VERSION 5.8 ;
BUSBITCHARS "[]" ;
DIVIDERCHAR "/" ;
UNITS
    DATABASE MICRONS 1000 ;
END UNITS

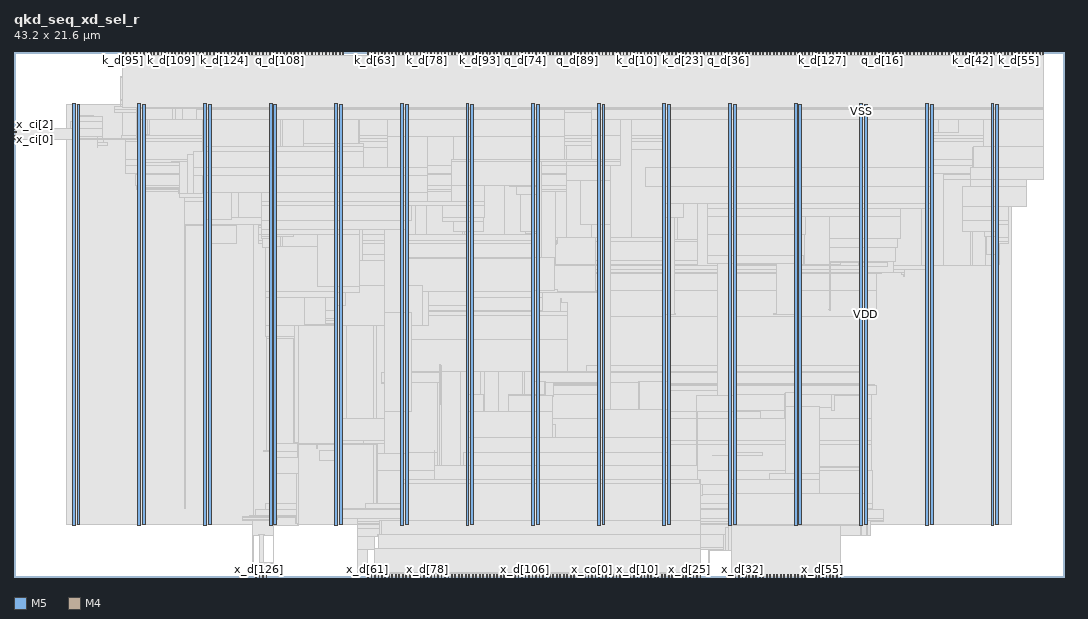
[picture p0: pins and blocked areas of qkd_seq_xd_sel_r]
MACRO qkd_seq_xd_sel_r
  FOREIGN qkd_seq_xd_sel_r 0 0 ;
  CLASS BLOCK ;
  SIZE 43.2 BY 21.6 ;
  PIN ck
    DIRECTION INPUT ;
    USE SIGNAL ;
    PORT
      LAYER M5 ;
        RECT  24.048 21.516 24.072 21.6 ;
    END
  END ck
  PIN k_d[0]
    DIRECTION INPUT ;
    USE SIGNAL ;
    PORT
      LAYER M5 ;
        RECT  24.192 21.516 24.216 21.6 ;
    END
  END k_d[0]
  PIN k_d[100]
    DIRECTION INPUT ;
    USE SIGNAL ;
    PORT
      LAYER M5 ;
        RECT  5.184 21.516 5.208 21.6 ;
    END
  END k_d[100]
  PIN k_d[101]
    DIRECTION INPUT ;
    USE SIGNAL ;
    PORT
      LAYER M5 ;
        RECT  5.328 21.516 5.352 21.6 ;
    END
  END k_d[101]
  PIN k_d[102]
    DIRECTION INPUT ;
    USE SIGNAL ;
    PORT
      LAYER M5 ;
        RECT  5.472 21.516 5.496 21.6 ;
    END
  END k_d[102]
  PIN k_d[103]
    DIRECTION INPUT ;
    USE SIGNAL ;
    PORT
      LAYER M5 ;
        RECT  5.616 21.516 5.64 21.6 ;
    END
  END k_d[103]
  PIN k_d[104]
    DIRECTION INPUT ;
    USE SIGNAL ;
    PORT
      LAYER M5 ;
        RECT  5.76 21.516 5.784 21.6 ;
    END
  END k_d[104]
  PIN k_d[105]
    DIRECTION INPUT ;
    USE SIGNAL ;
    PORT
      LAYER M5 ;
        RECT  5.904 21.516 5.928 21.6 ;
    END
  END k_d[105]
  PIN k_d[106]
    DIRECTION INPUT ;
    USE SIGNAL ;
    PORT
      LAYER M5 ;
        RECT  6.048 21.516 6.072 21.6 ;
    END
  END k_d[106]
  PIN k_d[107]
    DIRECTION INPUT ;
    USE SIGNAL ;
    PORT
      LAYER M5 ;
        RECT  6.192 21.516 6.216 21.6 ;
    END
  END k_d[107]
  PIN k_d[108]
    DIRECTION INPUT ;
    USE SIGNAL ;
    PORT
      LAYER M5 ;
        RECT  6.336 21.516 6.36 21.6 ;
    END
  END k_d[108]
  PIN k_d[109]
    DIRECTION INPUT ;
    USE SIGNAL ;
    PORT
      LAYER M5 ;
        RECT  6.48 21.516 6.504 21.6 ;
    END
  END k_d[109]
  PIN k_d[10]
    DIRECTION INPUT ;
    USE SIGNAL ;
    PORT
      LAYER M5 ;
        RECT  25.632 21.516 25.656 21.6 ;
    END
  END k_d[10]
  PIN k_d[110]
    DIRECTION INPUT ;
    USE SIGNAL ;
    PORT
      LAYER M5 ;
        RECT  6.624 21.516 6.648 21.6 ;
    END
  END k_d[110]
  PIN k_d[111]
    DIRECTION INPUT ;
    USE SIGNAL ;
    PORT
      LAYER M5 ;
        RECT  6.768 21.516 6.792 21.6 ;
    END
  END k_d[111]
  PIN k_d[112]
    DIRECTION INPUT ;
    USE SIGNAL ;
    PORT
      LAYER M5 ;
        RECT  6.912 21.516 6.936 21.6 ;
    END
  END k_d[112]
  PIN k_d[113]
    DIRECTION INPUT ;
    USE SIGNAL ;
    PORT
      LAYER M5 ;
        RECT  7.056 21.516 7.08 21.6 ;
    END
  END k_d[113]
  PIN k_d[114]
    DIRECTION INPUT ;
    USE SIGNAL ;
    PORT
      LAYER M5 ;
        RECT  7.2 21.516 7.224 21.6 ;
    END
  END k_d[114]
  PIN k_d[115]
    DIRECTION INPUT ;
    USE SIGNAL ;
    PORT
      LAYER M5 ;
        RECT  7.344 21.516 7.368 21.6 ;
    END
  END k_d[115]
  PIN k_d[116]
    DIRECTION INPUT ;
    USE SIGNAL ;
    PORT
      LAYER M5 ;
        RECT  7.488 21.516 7.512 21.6 ;
    END
  END k_d[116]
  PIN k_d[117]
    DIRECTION INPUT ;
    USE SIGNAL ;
    PORT
      LAYER M5 ;
        RECT  7.632 21.516 7.656 21.6 ;
    END
  END k_d[117]
  PIN k_d[118]
    DIRECTION INPUT ;
    USE SIGNAL ;
    PORT
      LAYER M5 ;
        RECT  7.776 21.516 7.8 21.6 ;
    END
  END k_d[118]
  PIN k_d[119]
    DIRECTION INPUT ;
    USE SIGNAL ;
    PORT
      LAYER M5 ;
        RECT  7.92 21.516 7.944 21.6 ;
    END
  END k_d[119]
  PIN k_d[11]
    DIRECTION INPUT ;
    USE SIGNAL ;
    PORT
      LAYER M5 ;
        RECT  25.776 21.516 25.8 21.6 ;
    END
  END k_d[11]
  PIN k_d[120]
    DIRECTION INPUT ;
    USE SIGNAL ;
    PORT
      LAYER M5 ;
        RECT  8.064 21.516 8.088 21.6 ;
    END
  END k_d[120]
  PIN k_d[121]
    DIRECTION INPUT ;
    USE SIGNAL ;
    PORT
      LAYER M5 ;
        RECT  8.208 21.516 8.232 21.6 ;
    END
  END k_d[121]
  PIN k_d[122]
    DIRECTION INPUT ;
    USE SIGNAL ;
    PORT
      LAYER M5 ;
        RECT  8.352 21.516 8.376 21.6 ;
    END
  END k_d[122]
  PIN k_d[123]
    DIRECTION INPUT ;
    USE SIGNAL ;
    PORT
      LAYER M5 ;
        RECT  8.496 21.516 8.52 21.6 ;
    END
  END k_d[123]
  PIN k_d[124]
    DIRECTION INPUT ;
    USE SIGNAL ;
    PORT
      LAYER M5 ;
        RECT  8.64 21.516 8.664 21.6 ;
    END
  END k_d[124]
  PIN k_d[125]
    DIRECTION INPUT ;
    USE SIGNAL ;
    PORT
      LAYER M5 ;
        RECT  8.784 21.516 8.808 21.6 ;
    END
  END k_d[125]
  PIN k_d[126]
    DIRECTION INPUT ;
    USE SIGNAL ;
    PORT
      LAYER M5 ;
        RECT  8.928 21.516 8.952 21.6 ;
    END
  END k_d[126]
  PIN k_d[127]
    DIRECTION INPUT ;
    USE SIGNAL ;
    PORT
      LAYER M5 ;
        RECT  33.264 21.516 33.288 21.6 ;
    END
  END k_d[127]
  PIN k_d[12]
    DIRECTION INPUT ;
    USE SIGNAL ;
    PORT
      LAYER M5 ;
        RECT  25.92 21.516 25.944 21.6 ;
    END
  END k_d[12]
  PIN k_d[13]
    DIRECTION INPUT ;
    USE SIGNAL ;
    PORT
      LAYER M5 ;
        RECT  26.064 21.516 26.088 21.6 ;
    END
  END k_d[13]
  PIN k_d[14]
    DIRECTION INPUT ;
    USE SIGNAL ;
    PORT
      LAYER M5 ;
        RECT  26.208 21.516 26.232 21.6 ;
    END
  END k_d[14]
  PIN k_d[15]
    DIRECTION INPUT ;
    USE SIGNAL ;
    PORT
      LAYER M5 ;
        RECT  26.352 21.516 26.376 21.6 ;
    END
  END k_d[15]
  PIN k_d[16]
    DIRECTION INPUT ;
    USE SIGNAL ;
    PORT
      LAYER M5 ;
        RECT  26.496 21.516 26.52 21.6 ;
    END
  END k_d[16]
  PIN k_d[17]
    DIRECTION INPUT ;
    USE SIGNAL ;
    PORT
      LAYER M5 ;
        RECT  26.64 21.516 26.664 21.6 ;
    END
  END k_d[17]
  PIN k_d[18]
    DIRECTION INPUT ;
    USE SIGNAL ;
    PORT
      LAYER M5 ;
        RECT  26.784 21.516 26.808 21.6 ;
    END
  END k_d[18]
  PIN k_d[19]
    DIRECTION INPUT ;
    USE SIGNAL ;
    PORT
      LAYER M5 ;
        RECT  26.928 21.516 26.952 21.6 ;
    END
  END k_d[19]
  PIN k_d[1]
    DIRECTION INPUT ;
    USE SIGNAL ;
    PORT
      LAYER M5 ;
        RECT  24.336 21.516 24.36 21.6 ;
    END
  END k_d[1]
  PIN k_d[20]
    DIRECTION INPUT ;
    USE SIGNAL ;
    PORT
      LAYER M5 ;
        RECT  27.072 21.516 27.096 21.6 ;
    END
  END k_d[20]
  PIN k_d[21]
    DIRECTION INPUT ;
    USE SIGNAL ;
    PORT
      LAYER M5 ;
        RECT  27.216 21.516 27.24 21.6 ;
    END
  END k_d[21]
  PIN k_d[22]
    DIRECTION INPUT ;
    USE SIGNAL ;
    PORT
      LAYER M5 ;
        RECT  27.36 21.516 27.384 21.6 ;
    END
  END k_d[22]
  PIN k_d[23]
    DIRECTION INPUT ;
    USE SIGNAL ;
    PORT
      LAYER M5 ;
        RECT  27.504 21.516 27.528 21.6 ;
    END
  END k_d[23]
  PIN k_d[24]
    DIRECTION INPUT ;
    USE SIGNAL ;
    PORT
      LAYER M5 ;
        RECT  27.648 21.516 27.672 21.6 ;
    END
  END k_d[24]
  PIN k_d[25]
    DIRECTION INPUT ;
    USE SIGNAL ;
    PORT
      LAYER M5 ;
        RECT  27.792 21.516 27.816 21.6 ;
    END
  END k_d[25]
  PIN k_d[26]
    DIRECTION INPUT ;
    USE SIGNAL ;
    PORT
      LAYER M5 ;
        RECT  27.936 21.516 27.96 21.6 ;
    END
  END k_d[26]
  PIN k_d[27]
    DIRECTION INPUT ;
    USE SIGNAL ;
    PORT
      LAYER M5 ;
        RECT  28.08 21.516 28.104 21.6 ;
    END
  END k_d[27]
  PIN k_d[28]
    DIRECTION INPUT ;
    USE SIGNAL ;
    PORT
      LAYER M5 ;
        RECT  28.224 21.516 28.248 21.6 ;
    END
  END k_d[28]
  PIN k_d[29]
    DIRECTION INPUT ;
    USE SIGNAL ;
    PORT
      LAYER M5 ;
        RECT  28.368 21.516 28.392 21.6 ;
    END
  END k_d[29]
  PIN k_d[2]
    DIRECTION INPUT ;
    USE SIGNAL ;
    PORT
      LAYER M5 ;
        RECT  24.48 21.516 24.504 21.6 ;
    END
  END k_d[2]
  PIN k_d[30]
    DIRECTION INPUT ;
    USE SIGNAL ;
    PORT
      LAYER M5 ;
        RECT  28.512 21.516 28.536 21.6 ;
    END
  END k_d[30]
  PIN k_d[31]
    DIRECTION INPUT ;
    USE SIGNAL ;
    PORT
      LAYER M5 ;
        RECT  37.872 21.516 37.896 21.6 ;
    END
  END k_d[31]
  PIN k_d[32]
    DIRECTION INPUT ;
    USE SIGNAL ;
    PORT
      LAYER M5 ;
        RECT  38.016 21.516 38.04 21.6 ;
    END
  END k_d[32]
  PIN k_d[33]
    DIRECTION INPUT ;
    USE SIGNAL ;
    PORT
      LAYER M5 ;
        RECT  38.16 21.516 38.184 21.6 ;
    END
  END k_d[33]
  PIN k_d[34]
    DIRECTION INPUT ;
    USE SIGNAL ;
    PORT
      LAYER M5 ;
        RECT  38.304 21.516 38.328 21.6 ;
    END
  END k_d[34]
  PIN k_d[35]
    DIRECTION INPUT ;
    USE SIGNAL ;
    PORT
      LAYER M5 ;
        RECT  38.448 21.516 38.472 21.6 ;
    END
  END k_d[35]
  PIN k_d[36]
    DIRECTION INPUT ;
    USE SIGNAL ;
    PORT
      LAYER M5 ;
        RECT  38.592 21.516 38.616 21.6 ;
    END
  END k_d[36]
  PIN k_d[37]
    DIRECTION INPUT ;
    USE SIGNAL ;
    PORT
      LAYER M5 ;
        RECT  38.736 21.516 38.76 21.6 ;
    END
  END k_d[37]
  PIN k_d[38]
    DIRECTION INPUT ;
    USE SIGNAL ;
    PORT
      LAYER M5 ;
        RECT  38.88 21.516 38.904 21.6 ;
    END
  END k_d[38]
  PIN k_d[39]
    DIRECTION INPUT ;
    USE SIGNAL ;
    PORT
      LAYER M5 ;
        RECT  39.024 21.516 39.048 21.6 ;
    END
  END k_d[39]
  PIN k_d[3]
    DIRECTION INPUT ;
    USE SIGNAL ;
    PORT
      LAYER M5 ;
        RECT  24.624 21.516 24.648 21.6 ;
    END
  END k_d[3]
  PIN k_d[40]
    DIRECTION INPUT ;
    USE SIGNAL ;
    PORT
      LAYER M5 ;
        RECT  39.168 21.516 39.192 21.6 ;
    END
  END k_d[40]
  PIN k_d[41]
    DIRECTION INPUT ;
    USE SIGNAL ;
    PORT
      LAYER M5 ;
        RECT  39.312 21.516 39.336 21.6 ;
    END
  END k_d[41]
  PIN k_d[42]
    DIRECTION INPUT ;
    USE SIGNAL ;
    PORT
      LAYER M5 ;
        RECT  39.456 21.516 39.48 21.6 ;
    END
  END k_d[42]
  PIN k_d[43]
    DIRECTION INPUT ;
    USE SIGNAL ;
    PORT
      LAYER M5 ;
        RECT  39.6 21.516 39.624 21.6 ;
    END
  END k_d[43]
  PIN k_d[44]
    DIRECTION INPUT ;
    USE SIGNAL ;
    PORT
      LAYER M5 ;
        RECT  39.744 21.516 39.768 21.6 ;
    END
  END k_d[44]
  PIN k_d[45]
    DIRECTION INPUT ;
    USE SIGNAL ;
    PORT
      LAYER M5 ;
        RECT  39.888 21.516 39.912 21.6 ;
    END
  END k_d[45]
  PIN k_d[46]
    DIRECTION INPUT ;
    USE SIGNAL ;
    PORT
      LAYER M5 ;
        RECT  40.032 21.516 40.056 21.6 ;
    END
  END k_d[46]
  PIN k_d[47]
    DIRECTION INPUT ;
    USE SIGNAL ;
    PORT
      LAYER M5 ;
        RECT  40.176 21.516 40.2 21.6 ;
    END
  END k_d[47]
  PIN k_d[48]
    DIRECTION INPUT ;
    USE SIGNAL ;
    PORT
      LAYER M5 ;
        RECT  40.32 21.516 40.344 21.6 ;
    END
  END k_d[48]
  PIN k_d[49]
    DIRECTION INPUT ;
    USE SIGNAL ;
    PORT
      LAYER M5 ;
        RECT  40.464 21.516 40.488 21.6 ;
    END
  END k_d[49]
  PIN k_d[4]
    DIRECTION INPUT ;
    USE SIGNAL ;
    PORT
      LAYER M5 ;
        RECT  24.768 21.516 24.792 21.6 ;
    END
  END k_d[4]
  PIN k_d[50]
    DIRECTION INPUT ;
    USE SIGNAL ;
    PORT
      LAYER M5 ;
        RECT  40.608 21.516 40.632 21.6 ;
    END
  END k_d[50]
  PIN k_d[51]
    DIRECTION INPUT ;
    USE SIGNAL ;
    PORT
      LAYER M5 ;
        RECT  40.752 21.516 40.776 21.6 ;
    END
  END k_d[51]
  PIN k_d[52]
    DIRECTION INPUT ;
    USE SIGNAL ;
    PORT
      LAYER M5 ;
        RECT  40.896 21.516 40.92 21.6 ;
    END
  END k_d[52]
  PIN k_d[53]
    DIRECTION INPUT ;
    USE SIGNAL ;
    PORT
      LAYER M5 ;
        RECT  41.04 21.516 41.064 21.6 ;
    END
  END k_d[53]
  PIN k_d[54]
    DIRECTION INPUT ;
    USE SIGNAL ;
    PORT
      LAYER M5 ;
        RECT  41.184 21.516 41.208 21.6 ;
    END
  END k_d[54]
  PIN k_d[55]
    DIRECTION INPUT ;
    USE SIGNAL ;
    PORT
      LAYER M5 ;
        RECT  41.328 21.516 41.352 21.6 ;
    END
  END k_d[55]
  PIN k_d[56]
    DIRECTION INPUT ;
    USE SIGNAL ;
    PORT
      LAYER M5 ;
        RECT  41.472 21.516 41.496 21.6 ;
    END
  END k_d[56]
  PIN k_d[57]
    DIRECTION INPUT ;
    USE SIGNAL ;
    PORT
      LAYER M5 ;
        RECT  41.616 21.516 41.64 21.6 ;
    END
  END k_d[57]
  PIN k_d[58]
    DIRECTION INPUT ;
    USE SIGNAL ;
    PORT
      LAYER M5 ;
        RECT  41.76 21.516 41.784 21.6 ;
    END
  END k_d[58]
  PIN k_d[59]
    DIRECTION INPUT ;
    USE SIGNAL ;
    PORT
      LAYER M5 ;
        RECT  41.904 21.516 41.928 21.6 ;
    END
  END k_d[59]
  PIN k_d[5]
    DIRECTION INPUT ;
    USE SIGNAL ;
    PORT
      LAYER M5 ;
        RECT  24.912 21.516 24.936 21.6 ;
    END
  END k_d[5]
  PIN k_d[60]
    DIRECTION INPUT ;
    USE SIGNAL ;
    PORT
      LAYER M5 ;
        RECT  42.048 21.516 42.072 21.6 ;
    END
  END k_d[60]
  PIN k_d[61]
    DIRECTION INPUT ;
    USE SIGNAL ;
    PORT
      LAYER M5 ;
        RECT  42.192 21.516 42.216 21.6 ;
    END
  END k_d[61]
  PIN k_d[62]
    DIRECTION INPUT ;
    USE SIGNAL ;
    PORT
      LAYER M5 ;
        RECT  42.336 21.516 42.36 21.6 ;
    END
  END k_d[62]
  PIN k_d[63]
    DIRECTION INPUT ;
    USE SIGNAL ;
    PORT
      LAYER M5 ;
        RECT  14.832 21.516 14.856 21.6 ;
    END
  END k_d[63]
  PIN k_d[64]
    DIRECTION INPUT ;
    USE SIGNAL ;
    PORT
      LAYER M5 ;
        RECT  14.976 21.516 15 21.6 ;
    END
  END k_d[64]
  PIN k_d[65]
    DIRECTION INPUT ;
    USE SIGNAL ;
    PORT
      LAYER M5 ;
        RECT  15.12 21.516 15.144 21.6 ;
    END
  END k_d[65]
  PIN k_d[66]
    DIRECTION INPUT ;
    USE SIGNAL ;
    PORT
      LAYER M5 ;
        RECT  15.264 21.516 15.288 21.6 ;
    END
  END k_d[66]
  PIN k_d[67]
    DIRECTION INPUT ;
    USE SIGNAL ;
    PORT
      LAYER M5 ;
        RECT  15.408 21.516 15.432 21.6 ;
    END
  END k_d[67]
  PIN k_d[68]
    DIRECTION INPUT ;
    USE SIGNAL ;
    PORT
      LAYER M5 ;
        RECT  15.552 21.516 15.576 21.6 ;
    END
  END k_d[68]
  PIN k_d[69]
    DIRECTION INPUT ;
    USE SIGNAL ;
    PORT
      LAYER M5 ;
        RECT  15.696 21.516 15.72 21.6 ;
    END
  END k_d[69]
  PIN k_d[6]
    DIRECTION INPUT ;
    USE SIGNAL ;
    PORT
      LAYER M5 ;
        RECT  25.056 21.516 25.08 21.6 ;
    END
  END k_d[6]
  PIN k_d[70]
    DIRECTION INPUT ;
    USE SIGNAL ;
    PORT
      LAYER M5 ;
        RECT  15.84 21.516 15.864 21.6 ;
    END
  END k_d[70]
  PIN k_d[71]
    DIRECTION INPUT ;
    USE SIGNAL ;
    PORT
      LAYER M5 ;
        RECT  15.984 21.516 16.008 21.6 ;
    END
  END k_d[71]
  PIN k_d[72]
    DIRECTION INPUT ;
    USE SIGNAL ;
    PORT
      LAYER M5 ;
        RECT  16.128 21.516 16.152 21.6 ;
    END
  END k_d[72]
  PIN k_d[73]
    DIRECTION INPUT ;
    USE SIGNAL ;
    PORT
      LAYER M5 ;
        RECT  16.272 21.516 16.296 21.6 ;
    END
  END k_d[73]
  PIN k_d[74]
    DIRECTION INPUT ;
    USE SIGNAL ;
    PORT
      LAYER M5 ;
        RECT  16.416 21.516 16.44 21.6 ;
    END
  END k_d[74]
  PIN k_d[75]
    DIRECTION INPUT ;
    USE SIGNAL ;
    PORT
      LAYER M5 ;
        RECT  16.56 21.516 16.584 21.6 ;
    END
  END k_d[75]
  PIN k_d[76]
    DIRECTION INPUT ;
    USE SIGNAL ;
    PORT
      LAYER M5 ;
        RECT  16.704 21.516 16.728 21.6 ;
    END
  END k_d[76]
  PIN k_d[77]
    DIRECTION INPUT ;
    USE SIGNAL ;
    PORT
      LAYER M5 ;
        RECT  16.848 21.516 16.872 21.6 ;
    END
  END k_d[77]
  PIN k_d[78]
    DIRECTION INPUT ;
    USE SIGNAL ;
    PORT
      LAYER M5 ;
        RECT  16.992 21.516 17.016 21.6 ;
    END
  END k_d[78]
  PIN k_d[79]
    DIRECTION INPUT ;
    USE SIGNAL ;
    PORT
      LAYER M5 ;
        RECT  17.136 21.516 17.16 21.6 ;
    END
  END k_d[79]
  PIN k_d[7]
    DIRECTION INPUT ;
    USE SIGNAL ;
    PORT
      LAYER M5 ;
        RECT  25.2 21.516 25.224 21.6 ;
    END
  END k_d[7]
  PIN k_d[80]
    DIRECTION INPUT ;
    USE SIGNAL ;
    PORT
      LAYER M5 ;
        RECT  17.28 21.516 17.304 21.6 ;
    END
  END k_d[80]
  PIN k_d[81]
    DIRECTION INPUT ;
    USE SIGNAL ;
    PORT
      LAYER M5 ;
        RECT  17.424 21.516 17.448 21.6 ;
    END
  END k_d[81]
  PIN k_d[82]
    DIRECTION INPUT ;
    USE SIGNAL ;
    PORT
      LAYER M5 ;
        RECT  17.568 21.516 17.592 21.6 ;
    END
  END k_d[82]
  PIN k_d[83]
    DIRECTION INPUT ;
    USE SIGNAL ;
    PORT
      LAYER M5 ;
        RECT  17.712 21.516 17.736 21.6 ;
    END
  END k_d[83]
  PIN k_d[84]
    DIRECTION INPUT ;
    USE SIGNAL ;
    PORT
      LAYER M5 ;
        RECT  17.856 21.516 17.88 21.6 ;
    END
  END k_d[84]
  PIN k_d[85]
    DIRECTION INPUT ;
    USE SIGNAL ;
    PORT
      LAYER M5 ;
        RECT  18 21.516 18.024 21.6 ;
    END
  END k_d[85]
  PIN k_d[86]
    DIRECTION INPUT ;
    USE SIGNAL ;
    PORT
      LAYER M5 ;
        RECT  18.144 21.516 18.168 21.6 ;
    END
  END k_d[86]
  PIN k_d[87]
    DIRECTION INPUT ;
    USE SIGNAL ;
    PORT
      LAYER M5 ;
        RECT  18.288 21.516 18.312 21.6 ;
    END
  END k_d[87]
  PIN k_d[88]
    DIRECTION INPUT ;
    USE SIGNAL ;
    PORT
      LAYER M5 ;
        RECT  18.432 21.516 18.456 21.6 ;
    END
  END k_d[88]
  PIN k_d[89]
    DIRECTION INPUT ;
    USE SIGNAL ;
    PORT
      LAYER M5 ;
        RECT  18.576 21.516 18.6 21.6 ;
    END
  END k_d[89]
  PIN k_d[8]
    DIRECTION INPUT ;
    USE SIGNAL ;
    PORT
      LAYER M5 ;
        RECT  25.344 21.516 25.368 21.6 ;
    END
  END k_d[8]
  PIN k_d[90]
    DIRECTION INPUT ;
    USE SIGNAL ;
    PORT
      LAYER M5 ;
        RECT  18.72 21.516 18.744 21.6 ;
    END
  END k_d[90]
  PIN k_d[91]
    DIRECTION INPUT ;
    USE SIGNAL ;
    PORT
      LAYER M5 ;
        RECT  18.864 21.516 18.888 21.6 ;
    END
  END k_d[91]
  PIN k_d[92]
    DIRECTION INPUT ;
    USE SIGNAL ;
    PORT
      LAYER M5 ;
        RECT  19.008 21.516 19.032 21.6 ;
    END
  END k_d[92]
  PIN k_d[93]
    DIRECTION INPUT ;
    USE SIGNAL ;
    PORT
      LAYER M5 ;
        RECT  19.152 21.516 19.176 21.6 ;
    END
  END k_d[93]
  PIN k_d[94]
    DIRECTION INPUT ;
    USE SIGNAL ;
    PORT
      LAYER M5 ;
        RECT  19.296 21.516 19.32 21.6 ;
    END
  END k_d[94]
  PIN k_d[95]
    DIRECTION INPUT ;
    USE SIGNAL ;
    PORT
      LAYER M5 ;
        RECT  4.464 21.516 4.488 21.6 ;
    END
  END k_d[95]
  PIN k_d[96]
    DIRECTION INPUT ;
    USE SIGNAL ;
    PORT
      LAYER M5 ;
        RECT  4.608 21.516 4.632 21.6 ;
    END
  END k_d[96]
  PIN k_d[97]
    DIRECTION INPUT ;
    USE SIGNAL ;
    PORT
      LAYER M5 ;
        RECT  4.752 21.516 4.776 21.6 ;
    END
  END k_d[97]
  PIN k_d[98]
    DIRECTION INPUT ;
    USE SIGNAL ;
    PORT
      LAYER M5 ;
        RECT  4.896 21.516 4.92 21.6 ;
    END
  END k_d[98]
  PIN k_d[99]
    DIRECTION INPUT ;
    USE SIGNAL ;
    PORT
      LAYER M5 ;
        RECT  5.04 21.516 5.064 21.6 ;
    END
  END k_d[99]
  PIN k_d[9]
    DIRECTION INPUT ;
    USE SIGNAL ;
    PORT
      LAYER M5 ;
        RECT  25.488 21.516 25.512 21.6 ;
    END
  END k_d[9]
  PIN q_d[0]
    DIRECTION INPUT ;
    USE SIGNAL ;
    PORT
      LAYER M5 ;
        RECT  33.408 21.516 33.432 21.6 ;
    END
  END q_d[0]
  PIN q_d[100]
    DIRECTION INPUT ;
    USE SIGNAL ;
    PORT
      LAYER M5 ;
        RECT  9.792 21.516 9.816 21.6 ;
    END
  END q_d[100]
  PIN q_d[101]
    DIRECTION INPUT ;
    USE SIGNAL ;
    PORT
      LAYER M5 ;
        RECT  9.936 21.516 9.96 21.6 ;
    END
  END q_d[101]
  PIN q_d[102]
    DIRECTION INPUT ;
    USE SIGNAL ;
    PORT
      LAYER M5 ;
        RECT  10.08 21.516 10.104 21.6 ;
    END
  END q_d[102]
  PIN q_d[103]
    DIRECTION INPUT ;
    USE SIGNAL ;
    PORT
      LAYER M5 ;
        RECT  10.224 21.516 10.248 21.6 ;
    END
  END q_d[103]
  PIN q_d[104]
    DIRECTION INPUT ;
    USE SIGNAL ;
    PORT
      LAYER M5 ;
        RECT  10.368 21.516 10.392 21.6 ;
    END
  END q_d[104]
  PIN q_d[105]
    DIRECTION INPUT ;
    USE SIGNAL ;
    PORT
      LAYER M5 ;
        RECT  10.512 21.516 10.536 21.6 ;
    END
  END q_d[105]
  PIN q_d[106]
    DIRECTION INPUT ;
    USE SIGNAL ;
    PORT
      LAYER M5 ;
        RECT  10.656 21.516 10.68 21.6 ;
    END
  END q_d[106]
  PIN q_d[107]
    DIRECTION INPUT ;
    USE SIGNAL ;
    PORT
      LAYER M5 ;
        RECT  10.8 21.516 10.824 21.6 ;
    END
  END q_d[107]
  PIN q_d[108]
    DIRECTION INPUT ;
    USE SIGNAL ;
    PORT
      LAYER M5 ;
        RECT  10.944 21.516 10.968 21.6 ;
    END
  END q_d[108]
  PIN q_d[109]
    DIRECTION INPUT ;
    USE SIGNAL ;
    PORT
      LAYER M5 ;
        RECT  11.088 21.516 11.112 21.6 ;
    END
  END q_d[109]
  PIN q_d[10]
    DIRECTION INPUT ;
    USE SIGNAL ;
    PORT
      LAYER M5 ;
        RECT  34.848 21.516 34.872 21.6 ;
    END
  END q_d[10]
  PIN q_d[110]
    DIRECTION INPUT ;
    USE SIGNAL ;
    PORT
      LAYER M5 ;
        RECT  11.232 21.516 11.256 21.6 ;
    END
  END q_d[110]
  PIN q_d[111]
    DIRECTION INPUT ;
    USE SIGNAL ;
    PORT
      LAYER M5 ;
        RECT  11.376 21.516 11.4 21.6 ;
    END
  END q_d[111]
  PIN q_d[112]
    DIRECTION INPUT ;
    USE SIGNAL ;
    PORT
      LAYER M5 ;
        RECT  11.52 21.516 11.544 21.6 ;
    END
  END q_d[112]
  PIN q_d[113]
    DIRECTION INPUT ;
    USE SIGNAL ;
    PORT
      LAYER M5 ;
        RECT  11.664 21.516 11.688 21.6 ;
    END
  END q_d[113]
  PIN q_d[114]
    DIRECTION INPUT ;
    USE SIGNAL ;
    PORT
      LAYER M5 ;
        RECT  11.808 21.516 11.832 21.6 ;
    END
  END q_d[114]
  PIN q_d[115]
    DIRECTION INPUT ;
    USE SIGNAL ;
    PORT
      LAYER M5 ;
        RECT  11.952 21.516 11.976 21.6 ;
    END
  END q_d[115]
  PIN q_d[116]
    DIRECTION INPUT ;
    USE SIGNAL ;
    PORT
      LAYER M5 ;
        RECT  12.096 21.516 12.12 21.6 ;
    END
  END q_d[116]
  PIN q_d[117]
    DIRECTION INPUT ;
    USE SIGNAL ;
    PORT
      LAYER M5 ;
        RECT  12.24 21.516 12.264 21.6 ;
    END
  END q_d[117]
  PIN q_d[118]
    DIRECTION INPUT ;
    USE SIGNAL ;
    PORT
      LAYER M5 ;
        RECT  12.384 21.516 12.408 21.6 ;
    END
  END q_d[118]
  PIN q_d[119]
    DIRECTION INPUT ;
    USE SIGNAL ;
    PORT
      LAYER M5 ;
        RECT  12.528 21.516 12.552 21.6 ;
    END
  END q_d[119]
  PIN q_d[11]
    DIRECTION INPUT ;
    USE SIGNAL ;
    PORT
      LAYER M5 ;
        RECT  34.992 21.516 35.016 21.6 ;
    END
  END q_d[11]
  PIN q_d[120]
    DIRECTION INPUT ;
    USE SIGNAL ;
    PORT
      LAYER M5 ;
        RECT  12.672 21.516 12.696 21.6 ;
    END
  END q_d[120]
  PIN q_d[121]
    DIRECTION INPUT ;
    USE SIGNAL ;
    PORT
      LAYER M5 ;
        RECT  12.816 21.516 12.84 21.6 ;
    END
  END q_d[121]
  PIN q_d[122]
    DIRECTION INPUT ;
    USE SIGNAL ;
    PORT
      LAYER M5 ;
        RECT  12.96 21.516 12.984 21.6 ;
    END
  END q_d[122]
  PIN q_d[123]
    DIRECTION INPUT ;
    USE SIGNAL ;
    PORT
      LAYER M5 ;
        RECT  13.104 21.516 13.128 21.6 ;
    END
  END q_d[123]
  PIN q_d[124]
    DIRECTION INPUT ;
    USE SIGNAL ;
    PORT
      LAYER M5 ;
        RECT  13.248 21.516 13.272 21.6 ;
    END
  END q_d[124]
  PIN q_d[125]
    DIRECTION INPUT ;
    USE SIGNAL ;
    PORT
      LAYER M5 ;
        RECT  13.392 21.516 13.416 21.6 ;
    END
  END q_d[125]
  PIN q_d[126]
    DIRECTION INPUT ;
    USE SIGNAL ;
    PORT
      LAYER M5 ;
        RECT  13.536 21.516 13.56 21.6 ;
    END
  END q_d[126]
  PIN q_d[127]
    DIRECTION INPUT ;
    USE SIGNAL ;
    PORT
      LAYER M5 ;
        RECT  14.544 21.516 14.568 21.6 ;
    END
  END q_d[127]
  PIN q_d[12]
    DIRECTION INPUT ;
    USE SIGNAL ;
    PORT
      LAYER M5 ;
        RECT  35.136 21.516 35.16 21.6 ;
    END
  END q_d[12]
  PIN q_d[13]
    DIRECTION INPUT ;
    USE SIGNAL ;
    PORT
      LAYER M5 ;
        RECT  35.28 21.516 35.304 21.6 ;
    END
  END q_d[13]
  PIN q_d[14]
    DIRECTION INPUT ;
    USE SIGNAL ;
    PORT
      LAYER M5 ;
        RECT  35.424 21.516 35.448 21.6 ;
    END
  END q_d[14]
  PIN q_d[15]
    DIRECTION INPUT ;
    USE SIGNAL ;
    PORT
      LAYER M5 ;
        RECT  35.568 21.516 35.592 21.6 ;
    END
  END q_d[15]
  PIN q_d[16]
    DIRECTION INPUT ;
    USE SIGNAL ;
    PORT
      LAYER M5 ;
        RECT  35.712 21.516 35.736 21.6 ;
    END
  END q_d[16]
  PIN q_d[17]
    DIRECTION INPUT ;
    USE SIGNAL ;
    PORT
      LAYER M5 ;
        RECT  35.856 21.516 35.88 21.6 ;
    END
  END q_d[17]
  PIN q_d[18]
    DIRECTION INPUT ;
    USE SIGNAL ;
    PORT
      LAYER M5 ;
        RECT  36 21.516 36.024 21.6 ;
    END
  END q_d[18]
  PIN q_d[19]
    DIRECTION INPUT ;
    USE SIGNAL ;
    PORT
      LAYER M5 ;
        RECT  36.144 21.516 36.168 21.6 ;
    END
  END q_d[19]
  PIN q_d[1]
    DIRECTION INPUT ;
    USE SIGNAL ;
    PORT
      LAYER M5 ;
        RECT  33.552 21.516 33.576 21.6 ;
    END
  END q_d[1]
  PIN q_d[20]
    DIRECTION INPUT ;
    USE SIGNAL ;
    PORT
      LAYER M5 ;
        RECT  36.288 21.516 36.312 21.6 ;
    END
  END q_d[20]
  PIN q_d[21]
    DIRECTION INPUT ;
    USE SIGNAL ;
    PORT
      LAYER M5 ;
        RECT  36.432 21.516 36.456 21.6 ;
    END
  END q_d[21]
  PIN q_d[22]
    DIRECTION INPUT ;
    USE SIGNAL ;
    PORT
      LAYER M5 ;
        RECT  36.576 21.516 36.6 21.6 ;
    END
  END q_d[22]
  PIN q_d[23]
    DIRECTION INPUT ;
    USE SIGNAL ;
    PORT
      LAYER M5 ;
        RECT  36.72 21.516 36.744 21.6 ;
    END
  END q_d[23]
  PIN q_d[24]
    DIRECTION INPUT ;
    USE SIGNAL ;
    PORT
      LAYER M5 ;
        RECT  36.864 21.516 36.888 21.6 ;
    END
  END q_d[24]
  PIN q_d[25]
    DIRECTION INPUT ;
    USE SIGNAL ;
    PORT
      LAYER M5 ;
        RECT  37.008 21.516 37.032 21.6 ;
    END
  END q_d[25]
  PIN q_d[26]
    DIRECTION INPUT ;
    USE SIGNAL ;
    PORT
      LAYER M5 ;
        RECT  37.152 21.516 37.176 21.6 ;
    END
  END q_d[26]
  PIN q_d[27]
    DIRECTION INPUT ;
    USE SIGNAL ;
    PORT
      LAYER M5 ;
        RECT  37.296 21.516 37.32 21.6 ;
    END
  END q_d[27]
  PIN q_d[28]
    DIRECTION INPUT ;
    USE SIGNAL ;
    PORT
      LAYER M5 ;
        RECT  37.44 21.516 37.464 21.6 ;
    END
  END q_d[28]
  PIN q_d[29]
    DIRECTION INPUT ;
    USE SIGNAL ;
    PORT
      LAYER M5 ;
        RECT  37.584 21.516 37.608 21.6 ;
    END
  END q_d[29]
  PIN q_d[2]
    DIRECTION INPUT ;
    USE SIGNAL ;
    PORT
      LAYER M5 ;
        RECT  33.696 21.516 33.72 21.6 ;
    END
  END q_d[2]
  PIN q_d[30]
    DIRECTION INPUT ;
    USE SIGNAL ;
    PORT
      LAYER M5 ;
        RECT  37.728 21.516 37.752 21.6 ;
    END
  END q_d[30]
  PIN q_d[31]
    DIRECTION INPUT ;
    USE SIGNAL ;
    PORT
      LAYER M5 ;
        RECT  28.656 21.516 28.68 21.6 ;
    END
  END q_d[31]
  PIN q_d[32]
    DIRECTION INPUT ;
    USE SIGNAL ;
    PORT
      LAYER M5 ;
        RECT  28.8 21.516 28.824 21.6 ;
    END
  END q_d[32]
  PIN q_d[33]
    DIRECTION INPUT ;
    USE SIGNAL ;
    PORT
      LAYER M5 ;
        RECT  28.944 21.516 28.968 21.6 ;
    END
  END q_d[33]
  PIN q_d[34]
    DIRECTION INPUT ;
    USE SIGNAL ;
    PORT
      LAYER M5 ;
        RECT  29.088 21.516 29.112 21.6 ;
    END
  END q_d[34]
  PIN q_d[35]
    DIRECTION INPUT ;
    USE SIGNAL ;
    PORT
      LAYER M5 ;
        RECT  29.232 21.516 29.256 21.6 ;
    END
  END q_d[35]
  PIN q_d[36]
    DIRECTION INPUT ;
    USE SIGNAL ;
    PORT
      LAYER M5 ;
        RECT  29.376 21.516 29.4 21.6 ;
    END
  END q_d[36]
  PIN q_d[37]
    DIRECTION INPUT ;
    USE SIGNAL ;
    PORT
      LAYER M5 ;
        RECT  29.52 21.516 29.544 21.6 ;
    END
  END q_d[37]
  PIN q_d[38]
    DIRECTION INPUT ;
    USE SIGNAL ;
    PORT
      LAYER M5 ;
        RECT  29.664 21.516 29.688 21.6 ;
    END
  END q_d[38]
  PIN q_d[39]
    DIRECTION INPUT ;
    USE SIGNAL ;
    PORT
      LAYER M5 ;
        RECT  29.808 21.516 29.832 21.6 ;
    END
  END q_d[39]
  PIN q_d[3]
    DIRECTION INPUT ;
    USE SIGNAL ;
    PORT
      LAYER M5 ;
        RECT  33.84 21.516 33.864 21.6 ;
    END
  END q_d[3]
  PIN q_d[40]
    DIRECTION INPUT ;
    USE SIGNAL ;
    PORT
      LAYER M5 ;
        RECT  29.952 21.516 29.976 21.6 ;
    END
  END q_d[40]
  PIN q_d[41]
    DIRECTION INPUT ;
    USE SIGNAL ;
    PORT
      LAYER M5 ;
        RECT  30.096 21.516 30.12 21.6 ;
    END
  END q_d[41]
  PIN q_d[42]
    DIRECTION INPUT ;
    USE SIGNAL ;
    PORT
      LAYER M5 ;
        RECT  30.24 21.516 30.264 21.6 ;
    END
  END q_d[42]
  PIN q_d[43]
    DIRECTION INPUT ;
    USE SIGNAL ;
    PORT
      LAYER M5 ;
        RECT  30.384 21.516 30.408 21.6 ;
    END
  END q_d[43]
  PIN q_d[44]
    DIRECTION INPUT ;
    USE SIGNAL ;
    PORT
      LAYER M5 ;
        RECT  30.528 21.516 30.552 21.6 ;
    END
  END q_d[44]
  PIN q_d[45]
    DIRECTION INPUT ;
    USE SIGNAL ;
    PORT
      LAYER M5 ;
        RECT  30.672 21.516 30.696 21.6 ;
    END
  END q_d[45]
  PIN q_d[46]
    DIRECTION INPUT ;
    USE SIGNAL ;
    PORT
      LAYER M5 ;
        RECT  30.816 21.516 30.84 21.6 ;
    END
  END q_d[46]
  PIN q_d[47]
    DIRECTION INPUT ;
    USE SIGNAL ;
    PORT
      LAYER M5 ;
        RECT  30.96 21.516 30.984 21.6 ;
    END
  END q_d[47]
  PIN q_d[48]
    DIRECTION INPUT ;
    USE SIGNAL ;
    PORT
      LAYER M5 ;
        RECT  31.104 21.516 31.128 21.6 ;
    END
  END q_d[48]
  PIN q_d[49]
    DIRECTION INPUT ;
    USE SIGNAL ;
    PORT
      LAYER M5 ;
        RECT  31.248 21.516 31.272 21.6 ;
    END
  END q_d[49]
  PIN q_d[4]
    DIRECTION INPUT ;
    USE SIGNAL ;
    PORT
      LAYER M5 ;
        RECT  33.984 21.516 34.008 21.6 ;
    END
  END q_d[4]
  PIN q_d[50]
    DIRECTION INPUT ;
    USE SIGNAL ;
    PORT
      LAYER M5 ;
        RECT  31.392 21.516 31.416 21.6 ;
    END
  END q_d[50]
  PIN q_d[51]
    DIRECTION INPUT ;
    USE SIGNAL ;
    PORT
      LAYER M5 ;
        RECT  31.536 21.516 31.56 21.6 ;
    END
  END q_d[51]
  PIN q_d[52]
    DIRECTION INPUT ;
    USE SIGNAL ;
    PORT
      LAYER M5 ;
        RECT  31.68 21.516 31.704 21.6 ;
    END
  END q_d[52]
  PIN q_d[53]
    DIRECTION INPUT ;
    USE SIGNAL ;
    PORT
      LAYER M5 ;
        RECT  31.824 21.516 31.848 21.6 ;
    END
  END q_d[53]
  PIN q_d[54]
    DIRECTION INPUT ;
    USE SIGNAL ;
    PORT
      LAYER M5 ;
        RECT  31.968 21.516 31.992 21.6 ;
    END
  END q_d[54]
  PIN q_d[55]
    DIRECTION INPUT ;
    USE SIGNAL ;
    PORT
      LAYER M5 ;
        RECT  32.112 21.516 32.136 21.6 ;
    END
  END q_d[55]
  PIN q_d[56]
    DIRECTION INPUT ;
    USE SIGNAL ;
    PORT
      LAYER M5 ;
        RECT  32.256 21.516 32.28 21.6 ;
    END
  END q_d[56]
  PIN q_d[57]
    DIRECTION INPUT ;
    USE SIGNAL ;
    PORT
      LAYER M5 ;
        RECT  32.4 21.516 32.424 21.6 ;
    END
  END q_d[57]
  PIN q_d[58]
    DIRECTION INPUT ;
    USE SIGNAL ;
    PORT
      LAYER M5 ;
        RECT  32.544 21.516 32.568 21.6 ;
    END
  END q_d[58]
  PIN q_d[59]
    DIRECTION INPUT ;
    USE SIGNAL ;
    PORT
      LAYER M5 ;
        RECT  32.688 21.516 32.712 21.6 ;
    END
  END q_d[59]
  PIN q_d[5]
    DIRECTION INPUT ;
    USE SIGNAL ;
    PORT
      LAYER M5 ;
        RECT  34.128 21.516 34.152 21.6 ;
    END
  END q_d[5]
  PIN q_d[60]
    DIRECTION INPUT ;
    USE SIGNAL ;
    PORT
      LAYER M5 ;
        RECT  32.832 21.516 32.856 21.6 ;
    END
  END q_d[60]
  PIN q_d[61]
    DIRECTION INPUT ;
    USE SIGNAL ;
    PORT
      LAYER M5 ;
        RECT  32.976 21.516 33 21.6 ;
    END
  END q_d[61]
  PIN q_d[62]
    DIRECTION INPUT ;
    USE SIGNAL ;
    PORT
      LAYER M5 ;
        RECT  33.12 21.516 33.144 21.6 ;
    END
  END q_d[62]
  PIN q_d[63]
    DIRECTION INPUT ;
    USE SIGNAL ;
    PORT
      LAYER M5 ;
        RECT  19.44 21.516 19.464 21.6 ;
    END
  END q_d[63]
  PIN q_d[64]
    DIRECTION INPUT ;
    USE SIGNAL ;
    PORT
      LAYER M5 ;
        RECT  19.584 21.516 19.608 21.6 ;
    END
  END q_d[64]
  PIN q_d[65]
    DIRECTION INPUT ;
    USE SIGNAL ;
    PORT
      LAYER M5 ;
        RECT  19.728 21.516 19.752 21.6 ;
    END
  END q_d[65]
  PIN q_d[66]
    DIRECTION INPUT ;
    USE SIGNAL ;
    PORT
      LAYER M5 ;
        RECT  19.872 21.516 19.896 21.6 ;
    END
  END q_d[66]
  PIN q_d[67]
    DIRECTION INPUT ;
    USE SIGNAL ;
    PORT
      LAYER M5 ;
        RECT  20.016 21.516 20.04 21.6 ;
    END
  END q_d[67]
  PIN q_d[68]
    DIRECTION INPUT ;
    USE SIGNAL ;
    PORT
      LAYER M5 ;
        RECT  20.16 21.516 20.184 21.6 ;
    END
  END q_d[68]
  PIN q_d[69]
    DIRECTION INPUT ;
    USE SIGNAL ;
    PORT
      LAYER M5 ;
        RECT  20.304 21.516 20.328 21.6 ;
    END
  END q_d[69]
  PIN q_d[6]
    DIRECTION INPUT ;
    USE SIGNAL ;
    PORT
      LAYER M5 ;
        RECT  34.272 21.516 34.296 21.6 ;
    END
  END q_d[6]
  PIN q_d[70]
    DIRECTION INPUT ;
    USE SIGNAL ;
    PORT
      LAYER M5 ;
        RECT  20.448 21.516 20.472 21.6 ;
    END
  END q_d[70]
  PIN q_d[71]
    DIRECTION INPUT ;
    USE SIGNAL ;
    PORT
      LAYER M5 ;
        RECT  20.592 21.516 20.616 21.6 ;
    END
  END q_d[71]
  PIN q_d[72]
    DIRECTION INPUT ;
    USE SIGNAL ;
    PORT
      LAYER M5 ;
        RECT  20.736 21.516 20.76 21.6 ;
    END
  END q_d[72]
  PIN q_d[73]
    DIRECTION INPUT ;
    USE SIGNAL ;
    PORT
      LAYER M5 ;
        RECT  20.88 21.516 20.904 21.6 ;
    END
  END q_d[73]
  PIN q_d[74]
    DIRECTION INPUT ;
    USE SIGNAL ;
    PORT
      LAYER M5 ;
        RECT  21.024 21.516 21.048 21.6 ;
    END
  END q_d[74]
  PIN q_d[75]
    DIRECTION INPUT ;
    USE SIGNAL ;
    PORT
      LAYER M5 ;
        RECT  21.168 21.516 21.192 21.6 ;
    END
  END q_d[75]
  PIN q_d[76]
    DIRECTION INPUT ;
    USE SIGNAL ;
    PORT
      LAYER M5 ;
        RECT  21.312 21.516 21.336 21.6 ;
    END
  END q_d[76]
  PIN q_d[77]
    DIRECTION INPUT ;
    USE SIGNAL ;
    PORT
      LAYER M5 ;
        RECT  21.456 21.516 21.48 21.6 ;
    END
  END q_d[77]
  PIN q_d[78]
    DIRECTION INPUT ;
    USE SIGNAL ;
    PORT
      LAYER M5 ;
        RECT  21.6 21.516 21.624 21.6 ;
    END
  END q_d[78]
  PIN q_d[79]
    DIRECTION INPUT ;
    USE SIGNAL ;
    PORT
      LAYER M5 ;
        RECT  21.744 21.516 21.768 21.6 ;
    END
  END q_d[79]
  PIN q_d[7]
    DIRECTION INPUT ;
    USE SIGNAL ;
    PORT
      LAYER M5 ;
        RECT  34.416 21.516 34.44 21.6 ;
    END
  END q_d[7]
  PIN q_d[80]
    DIRECTION INPUT ;
    USE SIGNAL ;
    PORT
      LAYER M5 ;
        RECT  21.888 21.516 21.912 21.6 ;
    END
  END q_d[80]
  PIN q_d[81]
    DIRECTION INPUT ;
    USE SIGNAL ;
    PORT
      LAYER M5 ;
        RECT  22.032 21.516 22.056 21.6 ;
    END
  END q_d[81]
  PIN q_d[82]
    DIRECTION INPUT ;
    USE SIGNAL ;
    PORT
      LAYER M5 ;
        RECT  22.176 21.516 22.2 21.6 ;
    END
  END q_d[82]
  PIN q_d[83]
    DIRECTION INPUT ;
    USE SIGNAL ;
    PORT
      LAYER M5 ;
        RECT  22.32 21.516 22.344 21.6 ;
    END
  END q_d[83]
  PIN q_d[84]
    DIRECTION INPUT ;
    USE SIGNAL ;
    PORT
      LAYER M5 ;
        RECT  22.464 21.516 22.488 21.6 ;
    END
  END q_d[84]
  PIN q_d[85]
    DIRECTION INPUT ;
    USE SIGNAL ;
    PORT
      LAYER M5 ;
        RECT  22.608 21.516 22.632 21.6 ;
    END
  END q_d[85]
  PIN q_d[86]
    DIRECTION INPUT ;
    USE SIGNAL ;
    PORT
      LAYER M5 ;
        RECT  22.752 21.516 22.776 21.6 ;
    END
  END q_d[86]
  PIN q_d[87]
    DIRECTION INPUT ;
    USE SIGNAL ;
    PORT
      LAYER M5 ;
        RECT  22.896 21.516 22.92 21.6 ;
    END
  END q_d[87]
  PIN q_d[88]
    DIRECTION INPUT ;
    USE SIGNAL ;
    PORT
      LAYER M5 ;
        RECT  23.04 21.516 23.064 21.6 ;
    END
  END q_d[88]
  PIN q_d[89]
    DIRECTION INPUT ;
    USE SIGNAL ;
    PORT
      LAYER M5 ;
        RECT  23.184 21.516 23.208 21.6 ;
    END
  END q_d[89]
  PIN q_d[8]
    DIRECTION INPUT ;
    USE SIGNAL ;
    PORT
      LAYER M5 ;
        RECT  34.56 21.516 34.584 21.6 ;
    END
  END q_d[8]
  PIN q_d[90]
    DIRECTION INPUT ;
    USE SIGNAL ;
    PORT
      LAYER M5 ;
        RECT  23.328 21.516 23.352 21.6 ;
    END
  END q_d[90]
  PIN q_d[91]
    DIRECTION INPUT ;
    USE SIGNAL ;
    PORT
      LAYER M5 ;
        RECT  23.472 21.516 23.496 21.6 ;
    END
  END q_d[91]
  PIN q_d[92]
    DIRECTION INPUT ;
    USE SIGNAL ;
    PORT
      LAYER M5 ;
        RECT  23.616 21.516 23.64 21.6 ;
    END
  END q_d[92]
  PIN q_d[93]
    DIRECTION INPUT ;
    USE SIGNAL ;
    PORT
      LAYER M5 ;
        RECT  23.76 21.516 23.784 21.6 ;
    END
  END q_d[93]
  PIN q_d[94]
    DIRECTION INPUT ;
    USE SIGNAL ;
    PORT
      LAYER M5 ;
        RECT  23.904 21.516 23.928 21.6 ;
    END
  END q_d[94]
  PIN q_d[95]
    DIRECTION INPUT ;
    USE SIGNAL ;
    PORT
      LAYER M5 ;
        RECT  9.072 21.516 9.096 21.6 ;
    END
  END q_d[95]
  PIN q_d[96]
    DIRECTION INPUT ;
    USE SIGNAL ;
    PORT
      LAYER M5 ;
        RECT  9.216 21.516 9.24 21.6 ;
    END
  END q_d[96]
  PIN q_d[97]
    DIRECTION INPUT ;
    USE SIGNAL ;
    PORT
      LAYER M5 ;
        RECT  9.36 21.516 9.384 21.6 ;
    END
  END q_d[97]
  PIN q_d[98]
    DIRECTION INPUT ;
    USE SIGNAL ;
    PORT
      LAYER M5 ;
        RECT  9.504 21.516 9.528 21.6 ;
    END
  END q_d[98]
  PIN q_d[99]
    DIRECTION INPUT ;
    USE SIGNAL ;
    PORT
      LAYER M5 ;
        RECT  9.648 21.516 9.672 21.6 ;
    END
  END q_d[99]
  PIN q_d[9]
    DIRECTION INPUT ;
    USE SIGNAL ;
    PORT
      LAYER M5 ;
        RECT  34.704 21.516 34.728 21.6 ;
    END
  END q_d[9]
  PIN q_v
    DIRECTION INPUT ;
    USE SIGNAL ;
    PORT
      LAYER M5 ;
        RECT  14.688 21.516 14.712 21.6 ;
    END
  END q_v
  PIN x_ci[0]
    DIRECTION INPUT ;
    USE SIGNAL ;
    PORT
      LAYER M4 ;
        RECT  0 18 0.084 18.024 ;
    END
  END x_ci[0]
  PIN x_ci[1]
    DIRECTION INPUT ;
    USE SIGNAL ;
    PORT
      LAYER M4 ;
        RECT  0 18.144 0.084 18.168 ;
    END
  END x_ci[1]
  PIN x_ci[2]
    DIRECTION INPUT ;
    USE SIGNAL ;
    PORT
      LAYER M4 ;
        RECT  0 18.288 0.084 18.312 ;
    END
  END x_ci[2]
  PIN x_co[0]
    DIRECTION OUTPUT ;
    USE SIGNAL ;
    PORT
      LAYER M5 ;
        RECT  23.76 0 23.784 0.084 ;
    END
  END x_co[0]
  PIN x_co[1]
    DIRECTION OUTPUT ;
    USE SIGNAL ;
    PORT
      LAYER M5 ;
        RECT  23.904 0 23.928 0.084 ;
    END
  END x_co[1]
  PIN x_co[2]
    DIRECTION OUTPUT ;
    USE SIGNAL ;
    PORT
      LAYER M5 ;
        RECT  24.048 0 24.072 0.084 ;
    END
  END x_co[2]
  PIN x_d[0]
    DIRECTION OUTPUT ;
    USE SIGNAL ;
    PORT
      LAYER M5 ;
        RECT  24.192 0 24.216 0.084 ;
    END
  END x_d[0]
  PIN x_d[100]
    DIRECTION OUTPUT ;
    USE SIGNAL ;
    PORT
      LAYER M5 ;
        RECT  20.16 0 20.184 0.084 ;
    END
  END x_d[100]
  PIN x_d[101]
    DIRECTION OUTPUT ;
    USE SIGNAL ;
    PORT
      LAYER M5 ;
        RECT  20.304 0 20.328 0.084 ;
    END
  END x_d[101]
  PIN x_d[102]
    DIRECTION OUTPUT ;
    USE SIGNAL ;
    PORT
      LAYER M5 ;
        RECT  20.448 0 20.472 0.084 ;
    END
  END x_d[102]
  PIN x_d[103]
    DIRECTION OUTPUT ;
    USE SIGNAL ;
    PORT
      LAYER M5 ;
        RECT  20.592 0 20.616 0.084 ;
    END
  END x_d[103]
  PIN x_d[104]
    DIRECTION OUTPUT ;
    USE SIGNAL ;
    PORT
      LAYER M5 ;
        RECT  20.736 0 20.76 0.084 ;
    END
  END x_d[104]
  PIN x_d[105]
    DIRECTION OUTPUT ;
    USE SIGNAL ;
    PORT
      LAYER M5 ;
        RECT  20.88 0 20.904 0.084 ;
    END
  END x_d[105]
  PIN x_d[106]
    DIRECTION OUTPUT ;
    USE SIGNAL ;
    PORT
      LAYER M5 ;
        RECT  21.024 0 21.048 0.084 ;
    END
  END x_d[106]
  PIN x_d[107]
    DIRECTION OUTPUT ;
    USE SIGNAL ;
    PORT
      LAYER M5 ;
        RECT  21.168 0 21.192 0.084 ;
    END
  END x_d[107]
  PIN x_d[108]
    DIRECTION OUTPUT ;
    USE SIGNAL ;
    PORT
      LAYER M5 ;
        RECT  21.312 0 21.336 0.084 ;
    END
  END x_d[108]
  PIN x_d[109]
    DIRECTION OUTPUT ;
    USE SIGNAL ;
    PORT
      LAYER M5 ;
        RECT  21.456 0 21.48 0.084 ;
    END
  END x_d[109]
  PIN x_d[10]
    DIRECTION OUTPUT ;
    USE SIGNAL ;
    PORT
      LAYER M5 ;
        RECT  25.632 0 25.656 0.084 ;
    END
  END x_d[10]
  PIN x_d[110]
    DIRECTION OUTPUT ;
    USE SIGNAL ;
    PORT
      LAYER M5 ;
        RECT  21.6 0 21.624 0.084 ;
    END
  END x_d[110]
  PIN x_d[111]
    DIRECTION OUTPUT ;
    USE SIGNAL ;
    PORT
      LAYER M5 ;
        RECT  21.744 0 21.768 0.084 ;
    END
  END x_d[111]
  PIN x_d[112]
    DIRECTION OUTPUT ;
    USE SIGNAL ;
    PORT
      LAYER M5 ;
        RECT  21.888 0 21.912 0.084 ;
    END
  END x_d[112]
  PIN x_d[113]
    DIRECTION OUTPUT ;
    USE SIGNAL ;
    PORT
      LAYER M5 ;
        RECT  22.032 0 22.056 0.084 ;
    END
  END x_d[113]
  PIN x_d[114]
    DIRECTION OUTPUT ;
    USE SIGNAL ;
    PORT
      LAYER M5 ;
        RECT  22.176 0 22.2 0.084 ;
    END
  END x_d[114]
  PIN x_d[115]
    DIRECTION OUTPUT ;
    USE SIGNAL ;
    PORT
      LAYER M5 ;
        RECT  22.32 0 22.344 0.084 ;
    END
  END x_d[115]
  PIN x_d[116]
    DIRECTION OUTPUT ;
    USE SIGNAL ;
    PORT
      LAYER M5 ;
        RECT  22.464 0 22.488 0.084 ;
    END
  END x_d[116]
  PIN x_d[117]
    DIRECTION OUTPUT ;
    USE SIGNAL ;
    PORT
      LAYER M5 ;
        RECT  22.608 0 22.632 0.084 ;
    END
  END x_d[117]
  PIN x_d[118]
    DIRECTION OUTPUT ;
    USE SIGNAL ;
    PORT
      LAYER M5 ;
        RECT  22.752 0 22.776 0.084 ;
    END
  END x_d[118]
  PIN x_d[119]
    DIRECTION OUTPUT ;
    USE SIGNAL ;
    PORT
      LAYER M5 ;
        RECT  22.896 0 22.92 0.084 ;
    END
  END x_d[119]
  PIN x_d[11]
    DIRECTION OUTPUT ;
    USE SIGNAL ;
    PORT
      LAYER M5 ;
        RECT  25.776 0 25.8 0.084 ;
    END
  END x_d[11]
  PIN x_d[120]
    DIRECTION OUTPUT ;
    USE SIGNAL ;
    PORT
      LAYER M5 ;
        RECT  23.04 0 23.064 0.084 ;
    END
  END x_d[120]
  PIN x_d[121]
    DIRECTION OUTPUT ;
    USE SIGNAL ;
    PORT
      LAYER M5 ;
        RECT  23.184 0 23.208 0.084 ;
    END
  END x_d[121]
  PIN x_d[122]
    DIRECTION OUTPUT ;
    USE SIGNAL ;
    PORT
      LAYER M5 ;
        RECT  23.328 0 23.352 0.084 ;
    END
  END x_d[122]
  PIN x_d[123]
    DIRECTION OUTPUT ;
    USE SIGNAL ;
    PORT
      LAYER M5 ;
        RECT  23.472 0 23.496 0.084 ;
    END
  END x_d[123]
  PIN x_d[124]
    DIRECTION OUTPUT ;
    USE SIGNAL ;
    PORT
      LAYER M5 ;
        RECT  23.616 0 23.64 0.084 ;
    END
  END x_d[124]
  PIN x_d[125]
    DIRECTION OUTPUT ;
    USE SIGNAL ;
    PORT
      LAYER M5 ;
        RECT  9.936 0 9.96 0.084 ;
    END
  END x_d[125]
  PIN x_d[126]
    DIRECTION OUTPUT ;
    USE SIGNAL ;
    PORT
      LAYER M5 ;
        RECT  10.08 0 10.104 0.084 ;
    END
  END x_d[126]
  PIN x_d[127]
    DIRECTION OUTPUT ;
    USE SIGNAL ;
    PORT
      LAYER M5 ;
        RECT  10.224 0 10.248 0.084 ;
    END
  END x_d[127]
  PIN x_d[12]
    DIRECTION OUTPUT ;
    USE SIGNAL ;
    PORT
      LAYER M5 ;
        RECT  25.92 0 25.944 0.084 ;
    END
  END x_d[12]
  PIN x_d[13]
    DIRECTION OUTPUT ;
    USE SIGNAL ;
    PORT
      LAYER M5 ;
        RECT  26.064 0 26.088 0.084 ;
    END
  END x_d[13]
  PIN x_d[14]
    DIRECTION OUTPUT ;
    USE SIGNAL ;
    PORT
      LAYER M5 ;
        RECT  26.208 0 26.232 0.084 ;
    END
  END x_d[14]
  PIN x_d[15]
    DIRECTION OUTPUT ;
    USE SIGNAL ;
    PORT
      LAYER M5 ;
        RECT  26.352 0 26.376 0.084 ;
    END
  END x_d[15]
  PIN x_d[16]
    DIRECTION OUTPUT ;
    USE SIGNAL ;
    PORT
      LAYER M5 ;
        RECT  26.496 0 26.52 0.084 ;
    END
  END x_d[16]
  PIN x_d[17]
    DIRECTION OUTPUT ;
    USE SIGNAL ;
    PORT
      LAYER M5 ;
        RECT  26.64 0 26.664 0.084 ;
    END
  END x_d[17]
  PIN x_d[18]
    DIRECTION OUTPUT ;
    USE SIGNAL ;
    PORT
      LAYER M5 ;
        RECT  26.784 0 26.808 0.084 ;
    END
  END x_d[18]
  PIN x_d[19]
    DIRECTION OUTPUT ;
    USE SIGNAL ;
    PORT
      LAYER M5 ;
        RECT  26.928 0 26.952 0.084 ;
    END
  END x_d[19]
  PIN x_d[1]
    DIRECTION OUTPUT ;
    USE SIGNAL ;
    PORT
      LAYER M5 ;
        RECT  24.336 0 24.36 0.084 ;
    END
  END x_d[1]
  PIN x_d[20]
    DIRECTION OUTPUT ;
    USE SIGNAL ;
    PORT
      LAYER M5 ;
        RECT  27.072 0 27.096 0.084 ;
    END
  END x_d[20]
  PIN x_d[21]
    DIRECTION OUTPUT ;
    USE SIGNAL ;
    PORT
      LAYER M5 ;
        RECT  27.216 0 27.24 0.084 ;
    END
  END x_d[21]
  PIN x_d[22]
    DIRECTION OUTPUT ;
    USE SIGNAL ;
    PORT
      LAYER M5 ;
        RECT  27.36 0 27.384 0.084 ;
    END
  END x_d[22]
  PIN x_d[23]
    DIRECTION OUTPUT ;
    USE SIGNAL ;
    PORT
      LAYER M5 ;
        RECT  27.504 0 27.528 0.084 ;
    END
  END x_d[23]
  PIN x_d[24]
    DIRECTION OUTPUT ;
    USE SIGNAL ;
    PORT
      LAYER M5 ;
        RECT  27.648 0 27.672 0.084 ;
    END
  END x_d[24]
  PIN x_d[25]
    DIRECTION OUTPUT ;
    USE SIGNAL ;
    PORT
      LAYER M5 ;
        RECT  27.792 0 27.816 0.084 ;
    END
  END x_d[25]
  PIN x_d[26]
    DIRECTION OUTPUT ;
    USE SIGNAL ;
    PORT
      LAYER M5 ;
        RECT  27.936 0 27.96 0.084 ;
    END
  END x_d[26]
  PIN x_d[27]
    DIRECTION OUTPUT ;
    USE SIGNAL ;
    PORT
      LAYER M5 ;
        RECT  28.08 0 28.104 0.084 ;
    END
  END x_d[27]
  PIN x_d[28]
    DIRECTION OUTPUT ;
    USE SIGNAL ;
    PORT
      LAYER M5 ;
        RECT  28.224 0 28.248 0.084 ;
    END
  END x_d[28]
  PIN x_d[29]
    DIRECTION OUTPUT ;
    USE SIGNAL ;
    PORT
      LAYER M5 ;
        RECT  29.52 0 29.544 0.084 ;
    END
  END x_d[29]
  PIN x_d[2]
    DIRECTION OUTPUT ;
    USE SIGNAL ;
    PORT
      LAYER M5 ;
        RECT  24.48 0 24.504 0.084 ;
    END
  END x_d[2]
  PIN x_d[30]
    DIRECTION OUTPUT ;
    USE SIGNAL ;
    PORT
      LAYER M5 ;
        RECT  29.664 0 29.688 0.084 ;
    END
  END x_d[30]
  PIN x_d[31]
    DIRECTION OUTPUT ;
    USE SIGNAL ;
    PORT
      LAYER M5 ;
        RECT  29.808 0 29.832 0.084 ;
    END
  END x_d[31]
  PIN x_d[32]
    DIRECTION OUTPUT ;
    USE SIGNAL ;
    PORT
      LAYER M5 ;
        RECT  29.952 0 29.976 0.084 ;
    END
  END x_d[32]
  PIN x_d[33]
    DIRECTION OUTPUT ;
    USE SIGNAL ;
    PORT
      LAYER M5 ;
        RECT  30.096 0 30.12 0.084 ;
    END
  END x_d[33]
  PIN x_d[34]
    DIRECTION OUTPUT ;
    USE SIGNAL ;
    PORT
      LAYER M5 ;
        RECT  30.24 0 30.264 0.084 ;
    END
  END x_d[34]
  PIN x_d[35]
    DIRECTION OUTPUT ;
    USE SIGNAL ;
    PORT
      LAYER M5 ;
        RECT  30.384 0 30.408 0.084 ;
    END
  END x_d[35]
  PIN x_d[36]
    DIRECTION OUTPUT ;
    USE SIGNAL ;
    PORT
      LAYER M5 ;
        RECT  30.528 0 30.552 0.084 ;
    END
  END x_d[36]
  PIN x_d[37]
    DIRECTION OUTPUT ;
    USE SIGNAL ;
    PORT
      LAYER M5 ;
        RECT  30.672 0 30.696 0.084 ;
    END
  END x_d[37]
  PIN x_d[38]
    DIRECTION OUTPUT ;
    USE SIGNAL ;
    PORT
      LAYER M5 ;
        RECT  30.816 0 30.84 0.084 ;
    END
  END x_d[38]
  PIN x_d[39]
    DIRECTION OUTPUT ;
    USE SIGNAL ;
    PORT
      LAYER M5 ;
        RECT  30.96 0 30.984 0.084 ;
    END
  END x_d[39]
  PIN x_d[3]
    DIRECTION OUTPUT ;
    USE SIGNAL ;
    PORT
      LAYER M5 ;
        RECT  24.624 0 24.648 0.084 ;
    END
  END x_d[3]
  PIN x_d[40]
    DIRECTION OUTPUT ;
    USE SIGNAL ;
    PORT
      LAYER M5 ;
        RECT  31.104 0 31.128 0.084 ;
    END
  END x_d[40]
  PIN x_d[41]
    DIRECTION OUTPUT ;
    USE SIGNAL ;
    PORT
      LAYER M5 ;
        RECT  31.248 0 31.272 0.084 ;
    END
  END x_d[41]
  PIN x_d[42]
    DIRECTION OUTPUT ;
    USE SIGNAL ;
    PORT
      LAYER M5 ;
        RECT  31.392 0 31.416 0.084 ;
    END
  END x_d[42]
  PIN x_d[43]
    DIRECTION OUTPUT ;
    USE SIGNAL ;
    PORT
      LAYER M5 ;
        RECT  31.536 0 31.56 0.084 ;
    END
  END x_d[43]
  PIN x_d[44]
    DIRECTION OUTPUT ;
    USE SIGNAL ;
    PORT
      LAYER M5 ;
        RECT  31.68 0 31.704 0.084 ;
    END
  END x_d[44]
  PIN x_d[45]
    DIRECTION OUTPUT ;
    USE SIGNAL ;
    PORT
      LAYER M5 ;
        RECT  31.824 0 31.848 0.084 ;
    END
  END x_d[45]
  PIN x_d[46]
    DIRECTION OUTPUT ;
    USE SIGNAL ;
    PORT
      LAYER M5 ;
        RECT  31.968 0 31.992 0.084 ;
    END
  END x_d[46]
  PIN x_d[47]
    DIRECTION OUTPUT ;
    USE SIGNAL ;
    PORT
      LAYER M5 ;
        RECT  32.112 0 32.136 0.084 ;
    END
  END x_d[47]
  PIN x_d[48]
    DIRECTION OUTPUT ;
    USE SIGNAL ;
    PORT
      LAYER M5 ;
        RECT  32.256 0 32.28 0.084 ;
    END
  END x_d[48]
  PIN x_d[49]
    DIRECTION OUTPUT ;
    USE SIGNAL ;
    PORT
      LAYER M5 ;
        RECT  32.4 0 32.424 0.084 ;
    END
  END x_d[49]
  PIN x_d[4]
    DIRECTION OUTPUT ;
    USE SIGNAL ;
    PORT
      LAYER M5 ;
        RECT  24.768 0 24.792 0.084 ;
    END
  END x_d[4]
  PIN x_d[50]
    DIRECTION OUTPUT ;
    USE SIGNAL ;
    PORT
      LAYER M5 ;
        RECT  32.544 0 32.568 0.084 ;
    END
  END x_d[50]
  PIN x_d[51]
    DIRECTION OUTPUT ;
    USE SIGNAL ;
    PORT
      LAYER M5 ;
        RECT  32.688 0 32.712 0.084 ;
    END
  END x_d[51]
  PIN x_d[52]
    DIRECTION OUTPUT ;
    USE SIGNAL ;
    PORT
      LAYER M5 ;
        RECT  32.832 0 32.856 0.084 ;
    END
  END x_d[52]
  PIN x_d[53]
    DIRECTION OUTPUT ;
    USE SIGNAL ;
    PORT
      LAYER M5 ;
        RECT  32.976 0 33 0.084 ;
    END
  END x_d[53]
  PIN x_d[54]
    DIRECTION OUTPUT ;
    USE SIGNAL ;
    PORT
      LAYER M5 ;
        RECT  33.12 0 33.144 0.084 ;
    END
  END x_d[54]
  PIN x_d[55]
    DIRECTION OUTPUT ;
    USE SIGNAL ;
    PORT
      LAYER M5 ;
        RECT  33.264 0 33.288 0.084 ;
    END
  END x_d[55]
  PIN x_d[56]
    DIRECTION OUTPUT ;
    USE SIGNAL ;
    PORT
      LAYER M5 ;
        RECT  33.408 0 33.432 0.084 ;
    END
  END x_d[56]
  PIN x_d[57]
    DIRECTION OUTPUT ;
    USE SIGNAL ;
    PORT
      LAYER M5 ;
        RECT  33.552 0 33.576 0.084 ;
    END
  END x_d[57]
  PIN x_d[58]
    DIRECTION OUTPUT ;
    USE SIGNAL ;
    PORT
      LAYER M5 ;
        RECT  33.696 0 33.72 0.084 ;
    END
  END x_d[58]
  PIN x_d[59]
    DIRECTION OUTPUT ;
    USE SIGNAL ;
    PORT
      LAYER M5 ;
        RECT  33.84 0 33.864 0.084 ;
    END
  END x_d[59]
  PIN x_d[5]
    DIRECTION OUTPUT ;
    USE SIGNAL ;
    PORT
      LAYER M5 ;
        RECT  24.912 0 24.936 0.084 ;
    END
  END x_d[5]
  PIN x_d[60]
    DIRECTION OUTPUT ;
    USE SIGNAL ;
    PORT
      LAYER M5 ;
        RECT  33.984 0 34.008 0.084 ;
    END
  END x_d[60]
  PIN x_d[61]
    DIRECTION OUTPUT ;
    USE SIGNAL ;
    PORT
      LAYER M5 ;
        RECT  14.544 0 14.568 0.084 ;
    END
  END x_d[61]
  PIN x_d[62]
    DIRECTION OUTPUT ;
    USE SIGNAL ;
    PORT
      LAYER M5 ;
        RECT  14.688 0 14.712 0.084 ;
    END
  END x_d[62]
  PIN x_d[63]
    DIRECTION OUTPUT ;
    USE SIGNAL ;
    PORT
      LAYER M5 ;
        RECT  14.832 0 14.856 0.084 ;
    END
  END x_d[63]
  PIN x_d[64]
    DIRECTION OUTPUT ;
    USE SIGNAL ;
    PORT
      LAYER M5 ;
        RECT  14.976 0 15 0.084 ;
    END
  END x_d[64]
  PIN x_d[65]
    DIRECTION OUTPUT ;
    USE SIGNAL ;
    PORT
      LAYER M5 ;
        RECT  15.12 0 15.144 0.084 ;
    END
  END x_d[65]
  PIN x_d[66]
    DIRECTION OUTPUT ;
    USE SIGNAL ;
    PORT
      LAYER M5 ;
        RECT  15.264 0 15.288 0.084 ;
    END
  END x_d[66]
  PIN x_d[67]
    DIRECTION OUTPUT ;
    USE SIGNAL ;
    PORT
      LAYER M5 ;
        RECT  15.408 0 15.432 0.084 ;
    END
  END x_d[67]
  PIN x_d[68]
    DIRECTION OUTPUT ;
    USE SIGNAL ;
    PORT
      LAYER M5 ;
        RECT  15.552 0 15.576 0.084 ;
    END
  END x_d[68]
  PIN x_d[69]
    DIRECTION OUTPUT ;
    USE SIGNAL ;
    PORT
      LAYER M5 ;
        RECT  15.696 0 15.72 0.084 ;
    END
  END x_d[69]
  PIN x_d[6]
    DIRECTION OUTPUT ;
    USE SIGNAL ;
    PORT
      LAYER M5 ;
        RECT  25.056 0 25.08 0.084 ;
    END
  END x_d[6]
  PIN x_d[70]
    DIRECTION OUTPUT ;
    USE SIGNAL ;
    PORT
      LAYER M5 ;
        RECT  15.84 0 15.864 0.084 ;
    END
  END x_d[70]
  PIN x_d[71]
    DIRECTION OUTPUT ;
    USE SIGNAL ;
    PORT
      LAYER M5 ;
        RECT  15.984 0 16.008 0.084 ;
    END
  END x_d[71]
  PIN x_d[72]
    DIRECTION OUTPUT ;
    USE SIGNAL ;
    PORT
      LAYER M5 ;
        RECT  16.128 0 16.152 0.084 ;
    END
  END x_d[72]
  PIN x_d[73]
    DIRECTION OUTPUT ;
    USE SIGNAL ;
    PORT
      LAYER M5 ;
        RECT  16.272 0 16.296 0.084 ;
    END
  END x_d[73]
  PIN x_d[74]
    DIRECTION OUTPUT ;
    USE SIGNAL ;
    PORT
      LAYER M5 ;
        RECT  16.416 0 16.44 0.084 ;
    END
  END x_d[74]
  PIN x_d[75]
    DIRECTION OUTPUT ;
    USE SIGNAL ;
    PORT
      LAYER M5 ;
        RECT  16.56 0 16.584 0.084 ;
    END
  END x_d[75]
  PIN x_d[76]
    DIRECTION OUTPUT ;
    USE SIGNAL ;
    PORT
      LAYER M5 ;
        RECT  16.704 0 16.728 0.084 ;
    END
  END x_d[76]
  PIN x_d[77]
    DIRECTION OUTPUT ;
    USE SIGNAL ;
    PORT
      LAYER M5 ;
        RECT  16.848 0 16.872 0.084 ;
    END
  END x_d[77]
  PIN x_d[78]
    DIRECTION OUTPUT ;
    USE SIGNAL ;
    PORT
      LAYER M5 ;
        RECT  16.992 0 17.016 0.084 ;
    END
  END x_d[78]
  PIN x_d[79]
    DIRECTION OUTPUT ;
    USE SIGNAL ;
    PORT
      LAYER M5 ;
        RECT  17.136 0 17.16 0.084 ;
    END
  END x_d[79]
  PIN x_d[7]
    DIRECTION OUTPUT ;
    USE SIGNAL ;
    PORT
      LAYER M5 ;
        RECT  25.2 0 25.224 0.084 ;
    END
  END x_d[7]
  PIN x_d[80]
    DIRECTION OUTPUT ;
    USE SIGNAL ;
    PORT
      LAYER M5 ;
        RECT  17.28 0 17.304 0.084 ;
    END
  END x_d[80]
  PIN x_d[81]
    DIRECTION OUTPUT ;
    USE SIGNAL ;
    PORT
      LAYER M5 ;
        RECT  17.424 0 17.448 0.084 ;
    END
  END x_d[81]
  PIN x_d[82]
    DIRECTION OUTPUT ;
    USE SIGNAL ;
    PORT
      LAYER M5 ;
        RECT  17.568 0 17.592 0.084 ;
    END
  END x_d[82]
  PIN x_d[83]
    DIRECTION OUTPUT ;
    USE SIGNAL ;
    PORT
      LAYER M5 ;
        RECT  17.712 0 17.736 0.084 ;
    END
  END x_d[83]
  PIN x_d[84]
    DIRECTION OUTPUT ;
    USE SIGNAL ;
    PORT
      LAYER M5 ;
        RECT  17.856 0 17.88 0.084 ;
    END
  END x_d[84]
  PIN x_d[85]
    DIRECTION OUTPUT ;
    USE SIGNAL ;
    PORT
      LAYER M5 ;
        RECT  18 0 18.024 0.084 ;
    END
  END x_d[85]
  PIN x_d[86]
    DIRECTION OUTPUT ;
    USE SIGNAL ;
    PORT
      LAYER M5 ;
        RECT  18.144 0 18.168 0.084 ;
    END
  END x_d[86]
  PIN x_d[87]
    DIRECTION OUTPUT ;
    USE SIGNAL ;
    PORT
      LAYER M5 ;
        RECT  18.288 0 18.312 0.084 ;
    END
  END x_d[87]
  PIN x_d[88]
    DIRECTION OUTPUT ;
    USE SIGNAL ;
    PORT
      LAYER M5 ;
        RECT  18.432 0 18.456 0.084 ;
    END
  END x_d[88]
  PIN x_d[89]
    DIRECTION OUTPUT ;
    USE SIGNAL ;
    PORT
      LAYER M5 ;
        RECT  18.576 0 18.6 0.084 ;
    END
  END x_d[89]
  PIN x_d[8]
    DIRECTION OUTPUT ;
    USE SIGNAL ;
    PORT
      LAYER M5 ;
        RECT  25.344 0 25.368 0.084 ;
    END
  END x_d[8]
  PIN x_d[90]
    DIRECTION OUTPUT ;
    USE SIGNAL ;
    PORT
      LAYER M5 ;
        RECT  18.72 0 18.744 0.084 ;
    END
  END x_d[90]
  PIN x_d[91]
    DIRECTION OUTPUT ;
    USE SIGNAL ;
    PORT
      LAYER M5 ;
        RECT  18.864 0 18.888 0.084 ;
    END
  END x_d[91]
  PIN x_d[92]
    DIRECTION OUTPUT ;
    USE SIGNAL ;
    PORT
      LAYER M5 ;
        RECT  19.008 0 19.032 0.084 ;
    END
  END x_d[92]
  PIN x_d[93]
    DIRECTION OUTPUT ;
    USE SIGNAL ;
    PORT
      LAYER M5 ;
        RECT  19.152 0 19.176 0.084 ;
    END
  END x_d[93]
  PIN x_d[94]
    DIRECTION OUTPUT ;
    USE SIGNAL ;
    PORT
      LAYER M5 ;
        RECT  19.296 0 19.32 0.084 ;
    END
  END x_d[94]
  PIN x_d[95]
    DIRECTION OUTPUT ;
    USE SIGNAL ;
    PORT
      LAYER M5 ;
        RECT  19.44 0 19.464 0.084 ;
    END
  END x_d[95]
  PIN x_d[96]
    DIRECTION OUTPUT ;
    USE SIGNAL ;
    PORT
      LAYER M5 ;
        RECT  19.584 0 19.608 0.084 ;
    END
  END x_d[96]
  PIN x_d[97]
    DIRECTION OUTPUT ;
    USE SIGNAL ;
    PORT
      LAYER M5 ;
        RECT  19.728 0 19.752 0.084 ;
    END
  END x_d[97]
  PIN x_d[98]
    DIRECTION OUTPUT ;
    USE SIGNAL ;
    PORT
      LAYER M5 ;
        RECT  19.872 0 19.896 0.084 ;
    END
  END x_d[98]
  PIN x_d[99]
    DIRECTION OUTPUT ;
    USE SIGNAL ;
    PORT
      LAYER M5 ;
        RECT  20.016 0 20.04 0.084 ;
    END
  END x_d[99]
  PIN x_d[9]
    DIRECTION OUTPUT ;
    USE SIGNAL ;
    PORT
      LAYER M5 ;
        RECT  25.488 0 25.512 0.084 ;
    END
  END x_d[9]
  PIN x_vi
    DIRECTION INPUT ;
    USE SIGNAL ;
    PORT
      LAYER M4 ;
        RECT  0 18.432 0.084 18.456 ;
    END
  END x_vi
  PIN x_vo
    DIRECTION OUTPUT ;
    USE SIGNAL ;
    PORT
      LAYER M5 ;
        RECT  10.368 0 10.392 0.084 ;
    END
  END x_vo
  PIN VDD
    DIRECTION INOUT ;
    USE POWER ;
    PORT
      LAYER M5 ;
        RECT  40.392 2.151 40.512 19.449 ;
        RECT  37.692 2.151 37.812 19.449 ;
        RECT  34.992 2.151 35.112 19.449 ;
        RECT  32.292 2.151 32.412 19.449 ;
        RECT  29.592 2.151 29.712 19.449 ;
        RECT  26.892 2.151 27.012 19.449 ;
        RECT  24.192 2.151 24.312 19.449 ;
        RECT  21.492 2.151 21.612 19.449 ;
        RECT  18.792 2.151 18.912 19.449 ;
        RECT  16.092 2.151 16.212 19.449 ;
        RECT  13.392 2.151 13.512 19.449 ;
        RECT  10.692 2.151 10.812 19.449 ;
        RECT  7.992 2.151 8.112 19.449 ;
        RECT  5.292 2.151 5.412 19.449 ;
        RECT  2.592 2.151 2.712 19.449 ;
    END
  END VDD
  PIN VSS
    DIRECTION INOUT ;
    USE GROUND ;
    PORT
      LAYER M5 ;
        RECT  40.2 2.137 40.32 19.463 ;
        RECT  37.5 2.137 37.62 19.463 ;
        RECT  34.8 2.137 34.92 19.463 ;
        RECT  32.1 2.137 32.22 19.463 ;
        RECT  29.4 2.137 29.52 19.463 ;
        RECT  26.7 2.137 26.82 19.463 ;
        RECT  24 2.137 24.12 19.463 ;
        RECT  21.3 2.137 21.42 19.463 ;
        RECT  18.6 2.137 18.72 19.463 ;
        RECT  15.9 2.137 16.02 19.463 ;
        RECT  13.2 2.137 13.32 19.463 ;
        RECT  10.5 2.137 10.62 19.463 ;
        RECT  7.8 2.137 7.92 19.463 ;
        RECT  5.1 2.137 5.22 19.463 ;
        RECT  2.4 2.137 2.52 19.463 ;
    END
  END VSS
  OBS
    LAYER RVTN ;
     RECT  2.16 2.16 41.04 2.295 ;
     RECT  2.16 2.565 41.04 2.835 ;
     RECT  2.16 3.105 41.04 3.375 ;
     RECT  2.16 3.645 41.04 3.915 ;
     RECT  2.16 4.185 41.04 4.455 ;
     RECT  2.16 4.725 41.04 4.995 ;
     RECT  2.16 5.265 41.04 5.535 ;
     RECT  2.16 5.805 41.04 6.075 ;
     RECT  2.16 6.345 41.04 6.615 ;
     RECT  2.16 6.885 41.04 7.155 ;
     RECT  2.16 7.425 41.04 7.695 ;
     RECT  2.16 7.965 41.04 8.235 ;
     RECT  2.16 8.505 41.04 8.775 ;
     RECT  2.16 9.045 41.04 9.315 ;
     RECT  2.16 9.585 41.04 9.855 ;
     RECT  2.16 10.125 41.04 10.395 ;
     RECT  2.16 10.665 41.04 10.935 ;
     RECT  2.16 11.205 41.04 11.475 ;
     RECT  2.16 11.745 41.04 12.015 ;
     RECT  2.16 12.285 41.04 12.555 ;
     RECT  2.16 12.825 41.04 13.095 ;
     RECT  2.16 13.365 41.04 13.635 ;
     RECT  2.16 13.905 41.04 14.175 ;
     RECT  2.16 14.445 41.04 14.715 ;
     RECT  2.16 14.985 41.04 15.255 ;
     RECT  2.16 15.525 41.04 15.795 ;
     RECT  2.16 16.065 41.04 16.335 ;
     RECT  2.16 16.605 41.04 16.875 ;
     RECT  2.16 17.145 41.04 17.415 ;
     RECT  2.16 17.685 41.04 17.955 ;
     RECT  2.16 18.225 41.04 18.495 ;
     RECT  2.16 18.765 41.04 19.035 ;
     RECT  2.16 19.305 41.04 19.44 ;
    LAYER RVTP ;
     RECT  2.16 2.295 41.04 2.565 ;
     RECT  2.16 2.835 41.04 3.105 ;
     RECT  2.16 3.375 41.04 3.645 ;
     RECT  2.16 3.915 41.04 4.185 ;
     RECT  2.16 4.455 41.04 4.725 ;
     RECT  2.16 4.995 41.04 5.265 ;
     RECT  2.16 5.535 41.04 5.805 ;
     RECT  2.16 6.075 41.04 6.345 ;
     RECT  2.16 6.615 41.04 6.885 ;
     RECT  2.16 7.155 41.04 7.425 ;
     RECT  2.16 7.695 41.04 7.965 ;
     RECT  2.16 8.235 41.04 8.505 ;
     RECT  2.16 8.775 41.04 9.045 ;
     RECT  2.16 9.315 41.04 9.585 ;
     RECT  2.16 9.855 41.04 10.125 ;
     RECT  2.16 10.395 41.04 10.665 ;
     RECT  2.16 10.935 41.04 11.205 ;
     RECT  2.16 11.475 41.04 11.745 ;
     RECT  2.16 12.015 41.04 12.285 ;
     RECT  2.16 12.555 41.04 12.825 ;
     RECT  2.16 13.095 41.04 13.365 ;
     RECT  2.16 13.635 41.04 13.905 ;
     RECT  2.16 14.175 41.04 14.445 ;
     RECT  2.16 14.715 41.04 14.985 ;
     RECT  2.16 15.255 41.04 15.525 ;
     RECT  2.16 15.795 41.04 16.065 ;
     RECT  2.16 16.335 41.04 16.605 ;
     RECT  2.16 16.875 41.04 17.145 ;
     RECT  2.16 17.415 41.04 17.685 ;
     RECT  2.16 17.955 41.04 18.225 ;
     RECT  2.16 18.495 41.04 18.765 ;
     RECT  2.16 19.035 41.04 19.305 ;
    LAYER M1 ;
     RECT  2.16 2.151 41.04 19.449 ;
    LAYER M2 ;
     RECT  2.16 2.151 9.859 19.449 ;
     RECT  9.859 2.106 11.687 19.449 ;
     RECT  11.687 2.151 14.791 19.449 ;
     RECT  14.791 2.106 14.899 19.449 ;
     RECT  14.899 2.034 15.719 19.449 ;
     RECT  15.719 2.151 16.447 19.449 ;
     RECT  16.447 2.106 16.699 19.449 ;
     RECT  16.699 2.07 17.095 19.449 ;
     RECT  17.095 1.998 17.987 19.449 ;
     RECT  17.987 2.106 18.167 19.449 ;
     RECT  18.167 2.151 26.095 19.449 ;
     RECT  26.095 2.106 28.679 19.449 ;
     RECT  28.679 2.151 41.04 19.449 ;
     RECT  41.04 16.578 41.531 18.018 ;
     RECT  41.531 16.92 41.819 18.018 ;
     RECT  41.819 16.92 41.963 16.938 ;
     RECT  41.819 17.928 42.107 18.018 ;
     RECT  42.107 17.928 42.251 17.946 ;
    LAYER M3 ;
     RECT  14.112 0.091 14.13 0.139 ;
     RECT  24.48 0.091 24.498 0.187 ;
     RECT  32.256 0.091 32.994 0.427 ;
     RECT  31.968 0.427 32.994 0.523 ;
     RECT  16.236 0.523 16.254 0.571 ;
     RECT  28.584 0.091 28.602 1.099 ;
     RECT  14.112 0.139 14.562 1.147 ;
     RECT  27.216 0.235 27.234 1.147 ;
     RECT  28.584 1.099 29.214 1.147 ;
     RECT  31.932 0.523 32.994 1.147 ;
     RECT  14.112 1.147 14.85 1.675 ;
     RECT  15.696 0.571 16.254 1.675 ;
     RECT  17.316 1.147 17.334 1.675 ;
     RECT  19.332 1.627 19.35 1.675 ;
     RECT  27.216 1.147 29.214 1.675 ;
     RECT  30.564 1.147 30.582 1.675 ;
     RECT  9.828 0.091 9.846 1.723 ;
     RECT  10.656 0.571 10.674 1.723 ;
     RECT  21.672 0.091 21.69 1.723 ;
     RECT  27.216 1.675 30.582 1.723 ;
     RECT  14.112 1.675 17.334 1.993 ;
     RECT  18.432 1.723 18.45 1.993 ;
     RECT  21.456 1.723 21.69 2.011 ;
     RECT  24.444 0.187 24.498 2.011 ;
     RECT  14.112 1.993 18.45 2.143 ;
     RECT  19.224 1.675 19.35 2.143 ;
     RECT  24.372 2.011 24.498 2.143 ;
     RECT  26.1 2.101 26.118 2.143 ;
     RECT  27.216 1.723 30.834 2.143 ;
     RECT  35.208 1.723 35.226 2.143 ;
     RECT  11.664 2.101 11.682 2.191 ;
     RECT  14.112 2.143 19.35 2.191 ;
     RECT  21.204 2.011 21.69 2.191 ;
     RECT  24.015 2.143 24.498 2.191 ;
     RECT  26.1 2.143 30.834 2.191 ;
     RECT  31.932 1.147 33.426 2.191 ;
     RECT  34.815 2.143 35.226 2.191 ;
     RECT  11.592 2.191 11.682 2.219 ;
     RECT  14.112 2.191 22.302 2.263 ;
     RECT  23.256 2.191 25.038 2.263 ;
     RECT  26.1 2.191 35.226 2.263 ;
     RECT  14.112 2.263 35.226 2.299 ;
     RECT  9.828 1.723 10.674 2.335 ;
     RECT  9.396 2.335 10.674 2.371 ;
     RECT  2.415 2.143 2.505 2.413 ;
     RECT  5.115 2.143 5.205 2.413 ;
     RECT  7.815 2.143 7.905 2.413 ;
     RECT  13.215 2.143 13.305 2.413 ;
     RECT  14.112 2.299 35.766 2.413 ;
     RECT  37.515 2.143 37.605 2.413 ;
     RECT  40.215 2.143 40.305 2.413 ;
     RECT  9.396 2.371 10.854 2.461 ;
     RECT  11.592 2.219 11.61 2.461 ;
     RECT  9.396 2.461 11.61 2.489 ;
     RECT  9.684 2.489 11.61 2.525 ;
     RECT  9.936 2.525 11.61 2.759 ;
     RECT  13.215 2.413 35.766 2.759 ;
     RECT  10.296 2.759 11.61 2.795 ;
     RECT  13.215 2.759 35.334 2.831 ;
     RECT  10.332 2.795 11.61 3.029 ;
     RECT  14.472 2.831 35.334 3.029 ;
     RECT  10.515 3.029 11.61 4.261 ;
     RECT  14.94 3.029 35.334 4.379 ;
     RECT  13.215 2.831 13.497 4.801 ;
     RECT  10.515 4.261 11.718 4.919 ;
     RECT  10.515 4.919 11.646 5.161 ;
     RECT  12.564 4.801 13.497 5.189 ;
     RECT  10.26 5.161 11.646 5.213 ;
     RECT  12.456 5.305 12.474 5.459 ;
     RECT  14.94 4.379 35.262 5.467 ;
     RECT  11.52 5.213 11.646 5.518 ;
     RECT  13.215 5.189 13.497 5.611 ;
     RECT  14.364 5.467 35.262 5.611 ;
     RECT  13.215 5.611 35.262 6.539 ;
     RECT  15.264 6.539 35.262 7.501 ;
     RECT  15.264 7.501 35.478 7.889 ;
     RECT  15.264 7.889 35.406 7.925 ;
     RECT  15.264 7.925 35.097 7.963 ;
     RECT  15.12 7.963 35.097 8.429 ;
     RECT  15.3 8.429 35.097 8.465 ;
     RECT  23.544 8.465 35.097 8.699 ;
     RECT  15.3 8.465 22.77 9.779 ;
     RECT  10.404 5.213 10.797 9.823 ;
     RECT  11.52 5.518 11.538 9.823 ;
     RECT  10.404 9.823 11.538 9.895 ;
     RECT  10.332 9.895 11.538 10.363 ;
     RECT  13.215 6.539 13.662 10.435 ;
     RECT  12.816 10.435 13.662 10.561 ;
     RECT  12.816 10.561 13.77 10.633 ;
     RECT  24.015 8.699 35.097 10.705 ;
     RECT  15.336 9.779 22.77 10.741 ;
     RECT  15.012 10.741 22.77 10.903 ;
     RECT  14.832 10.903 22.77 10.931 ;
     RECT  12.816 10.633 14.094 10.975 ;
     RECT  14.832 10.931 21.762 10.975 ;
     RECT  22.5 10.931 22.77 11.309 ;
     RECT  22.5 11.309 22.518 11.471 ;
     RECT  10.332 10.363 11.97 11.515 ;
     RECT  12.816 10.975 21.762 11.515 ;
     RECT  10.332 11.515 21.762 11.741 ;
     RECT  24.015 10.705 35.478 11.785 ;
     RECT  22.32 11.785 22.338 11.837 ;
     RECT  36.612 12.361 36.63 12.451 ;
     RECT  23.94 11.785 35.478 12.487 ;
     RECT  23.94 12.487 35.694 12.523 ;
     RECT  36.504 12.451 36.63 12.523 ;
     RECT  23.94 12.523 36.63 12.631 ;
     RECT  37.515 2.413 37.797 12.631 ;
     RECT  40.215 2.413 40.497 12.811 ;
     RECT  23.94 12.631 37.797 12.829 ;
     RECT  23.94 12.829 38.25 12.859 ;
     RECT  39.924 12.811 40.497 12.859 ;
     RECT  39.924 12.859 40.554 12.955 ;
     RECT  39.816 12.955 40.554 12.991 ;
     RECT  23.94 12.859 38.898 13.037 ;
     RECT  39.744 12.991 40.554 13.171 ;
     RECT  7.815 2.413 8.097 13.711 ;
     RECT  10.332 11.741 21.597 13.711 ;
     RECT  22.32 13.675 22.338 13.711 ;
     RECT  39.42 13.171 40.554 13.711 ;
     RECT  23.94 13.037 38.646 13.801 ;
     RECT  39.42 13.711 40.914 13.801 ;
     RECT  10.044 13.711 21.597 13.837 ;
     RECT  22.32 13.711 22.374 13.837 ;
     RECT  23.94 13.801 40.914 13.963 ;
     RECT  10.044 13.837 22.374 14.071 ;
     RECT  10.044 14.071 22.95 14.395 ;
     RECT  10.044 14.395 22.986 14.443 ;
     RECT  7.02 2.803 7.038 14.449 ;
     RECT  7.815 13.711 9.162 14.449 ;
     RECT  7.02 14.449 9.162 14.485 ;
     RECT  10.044 14.443 23.166 14.485 ;
     RECT  23.904 13.963 40.914 14.485 ;
     RECT  7.02 14.485 40.914 15.449 ;
     RECT  7.02 15.449 40.842 15.601 ;
     RECT  6.804 15.601 40.842 15.787 ;
     RECT  5.115 2.413 5.397 15.871 ;
     RECT  6.768 15.787 40.842 15.871 ;
     RECT  5.115 15.871 40.842 15.961 ;
     RECT  5.04 15.961 40.842 16.105 ;
     RECT  5.004 16.105 40.842 16.573 ;
     RECT  5.004 16.573 41.526 16.609 ;
     RECT  4.608 16.609 41.526 16.915 ;
     RECT  4.572 16.915 41.958 17.177 ;
     RECT  3.42 17.653 3.438 17.761 ;
     RECT  3.42 17.761 3.834 17.879 ;
     RECT  4.608 17.177 41.958 17.923 ;
     RECT  2.415 2.413 2.697 17.989 ;
     RECT  4.608 17.923 42.246 18.031 ;
     RECT  3.42 17.879 3.69 18.059 ;
     RECT  2.304 17.989 2.697 18.121 ;
     RECT  3.42 18.059 3.654 18.121 ;
     RECT  4.428 18.031 42.246 18.149 ;
     RECT  2.304 18.121 3.654 18.455 ;
     RECT  2.34 18.455 3.654 18.725 ;
     RECT  2.415 18.725 3.654 18.959 ;
     RECT  2.415 18.959 3.258 18.995 ;
     RECT  4.464 18.149 42.246 19.111 ;
     RECT  2.415 18.995 2.697 19.187 ;
     RECT  4.14 19.111 42.246 19.229 ;
     RECT  21.132 19.229 29.574 19.301 ;
     RECT  34.74 19.229 42.246 19.301 ;
     RECT  30.312 19.229 32.67 19.325 ;
     RECT  4.14 19.229 13.662 19.373 ;
     RECT  14.76 19.229 20.394 19.373 ;
     RECT  21.132 19.301 21.69 19.373 ;
     RECT  22.428 19.301 29.574 19.373 ;
     RECT  30.456 19.325 32.598 19.373 ;
     RECT  33.516 19.229 33.966 19.373 ;
     RECT  34.74 19.301 36.63 19.373 ;
     RECT  37.515 19.301 42.246 19.373 ;
     RECT  4.392 19.373 5.706 19.421 ;
     RECT  2.415 19.187 2.505 19.457 ;
     RECT  4.392 19.421 5.205 19.457 ;
     RECT  10.515 19.373 11.034 19.457 ;
     RECT  13.215 19.373 13.662 19.457 ;
     RECT  24.015 19.373 24.93 19.457 ;
     RECT  29.415 19.373 29.574 19.457 ;
     RECT  32.115 19.373 32.526 19.457 ;
     RECT  37.515 19.373 38.034 19.457 ;
     RECT  40.215 19.373 42.246 19.457 ;
     RECT  10.944 19.457 11.034 19.565 ;
     RECT  13.356 19.457 13.662 19.565 ;
     RECT  15.768 19.373 16.578 19.565 ;
     RECT  18.576 19.373 18.954 19.565 ;
     RECT  21.24 19.373 21.69 19.565 ;
     RECT  24.192 19.457 24.93 19.565 ;
     RECT  32.436 19.457 32.526 19.565 ;
     RECT  34.74 19.373 35.01 19.565 ;
     RECT  37.944 19.457 38.034 19.565 ;
     RECT  4.392 19.457 5.094 19.613 ;
     RECT  7.776 19.373 7.974 19.613 ;
     RECT  10.944 19.565 10.962 19.613 ;
     RECT  13.644 19.565 13.662 19.613 ;
     RECT  15.768 19.565 15.822 19.613 ;
     RECT  18.576 19.565 18.774 19.613 ;
     RECT  21.24 19.565 21.258 19.613 ;
     RECT  26.676 19.373 27.306 19.613 ;
     RECT  34.74 19.565 34.758 19.613 ;
     RECT  38.016 19.565 38.034 19.613 ;
     RECT  4.392 19.613 5.022 19.661 ;
     RECT  32.436 19.565 32.454 19.901 ;
     RECT  6.66 19.373 6.678 19.997 ;
     RECT  14.76 19.373 14.778 19.997 ;
     RECT  40.716 19.457 42.246 19.997 ;
     RECT  24.48 19.565 24.93 20.525 ;
     RECT  29.556 19.457 29.574 20.525 ;
     RECT  4.392 19.661 4.95 20.573 ;
     RECT  15.768 19.613 15.786 20.573 ;
     RECT  16.56 19.565 16.578 20.573 ;
     RECT  23.004 19.373 23.022 21.485 ;
     RECT  24.912 20.525 24.93 21.485 ;
     RECT  36.612 19.373 36.63 21.485 ;
     RECT  40.932 19.997 42.246 21.485 ;
    LAYER M4 ;
     RECT  0.06 18 2.408 18.456 ;
     RECT  2.408 2.148 2.512 19.452 ;
     RECT  2.512 2.418 2.704 19.182 ;
     RECT  4.381 20.544 4.453 20.568 ;
     RECT  4.129 19.344 4.669 19.368 ;
     RECT  4.453 20.496 4.669 20.568 ;
     RECT  2.704 18 5.029 18.024 ;
     RECT  4.669 19.344 5.029 20.568 ;
     RECT  5.029 18 5.108 20.568 ;
     RECT  5.108 2.148 5.212 20.568 ;
     RECT  5.212 2.418 5.219 20.568 ;
     RECT  5.219 2.418 5.404 19.608 ;
     RECT  5.404 18.192 5.507 19.608 ;
     RECT  5.507 18.192 5.573 19.416 ;
     RECT  5.404 17.04 6.469 17.064 ;
     RECT  5.573 18.816 6.649 19.416 ;
     RECT  5.404 15.984 6.757 16.008 ;
     RECT  6.757 15.792 6.793 16.008 ;
     RECT  6.469 17.04 6.793 17.112 ;
     RECT  6.649 18.816 6.947 19.992 ;
     RECT  6.793 15.792 7.153 17.112 ;
     RECT  7.153 15.792 7.381 17.4 ;
     RECT  7.381 15.792 7.765 17.496 ;
     RECT  6.947 18.816 7.765 19.608 ;
     RECT  7.765 15.792 7.808 19.608 ;
     RECT  7.808 2.148 7.912 19.608 ;
     RECT  7.912 2.418 7.985 19.608 ;
     RECT  7.985 2.418 8.104 19.368 ;
     RECT  8.053 21.264 8.197 21.288 ;
     RECT  8.197 21.264 8.243 21.384 ;
     RECT  8.243 21.36 8.339 21.384 ;
     RECT  8.104 14.736 8.965 19.368 ;
     RECT  8.965 14.784 9.251 19.368 ;
     RECT  9.817 0.096 9.971 0.12 ;
     RECT  9.251 14.784 10.165 17.688 ;
     RECT  10.165 13.92 10.213 17.688 ;
     RECT  9.251 18.816 10.213 19.368 ;
     RECT  10.061 1.728 10.297 1.752 ;
     RECT  10.213 13.584 10.309 17.736 ;
     RECT  10.213 18.72 10.309 19.368 ;
     RECT  10.249 5.184 10.508 5.208 ;
     RECT  10.309 13.584 10.508 19.368 ;
     RECT  10.309 21.408 10.547 21.432 ;
     RECT  10.508 2.148 10.612 19.452 ;
     RECT  10.612 2.418 10.645 19.452 ;
     RECT  10.357 0.576 10.685 0.6 ;
     RECT  10.645 2.418 10.804 19.608 ;
     RECT  10.804 13.584 10.973 19.608 ;
     RECT  10.973 13.584 11.045 19.56 ;
     RECT  10.804 5.184 11.657 5.496 ;
     RECT  12.469 11.952 12.805 11.976 ;
     RECT  11.045 13.584 12.805 19.368 ;
     RECT  11.657 5.472 13.208 5.496 ;
     RECT  11.941 10.368 13.208 10.392 ;
     RECT  12.805 11.952 13.208 19.368 ;
     RECT  13.208 2.148 13.237 19.452 ;
     RECT  13.237 2.148 13.312 19.608 ;
     RECT  13.312 2.418 13.504 19.608 ;
     RECT  13.093 21.408 13.525 21.432 ;
     RECT  13.525 21.312 13.619 21.432 ;
     RECT  13.619 21.312 13.667 21.336 ;
     RECT  13.504 13.008 13.673 19.608 ;
     RECT  13.673 13.008 14.221 18.84 ;
     RECT  14.221 13.008 14.357 17.832 ;
     RECT  14.357 14.304 14.387 17.832 ;
     RECT  14.101 0.096 14.533 0.12 ;
     RECT  14.533 0.096 14.579 0.168 ;
     RECT  14.579 0.144 14.723 0.168 ;
     RECT  14.821 1.152 14.905 1.176 ;
     RECT  13.504 5.472 14.965 5.496 ;
     RECT  14.221 18.816 14.965 18.84 ;
     RECT  14.749 19.968 14.965 19.992 ;
     RECT  14.965 1.68 15.037 1.752 ;
     RECT  14.965 5.088 15.253 5.496 ;
     RECT  14.387 14.304 15.349 17.688 ;
     RECT  14.965 18.816 15.349 19.992 ;
     RECT  15.037 1.68 15.443 2.328 ;
     RECT  14.357 13.008 15.685 13.272 ;
     RECT  15.349 14.304 15.685 19.992 ;
     RECT  15.685 13.008 15.757 19.992 ;
     RECT  15.397 21.408 15.757 21.432 ;
     RECT  15.685 0.576 15.769 0.6 ;
     RECT  15.757 13.008 15.875 21.432 ;
     RECT  15.443 1.968 15.908 2.328 ;
     RECT  15.253 5.088 15.908 6.024 ;
     RECT  15.109 7.968 15.908 7.992 ;
     RECT  13.504 10.368 15.908 11.976 ;
     RECT  15.875 13.008 15.908 19.56 ;
     RECT  15.908 1.968 16.204 19.56 ;
     RECT  16.117 0.144 16.307 0.552 ;
     RECT  16.307 0.144 16.355 0.168 ;
     RECT  15.875 20.544 16.403 21.432 ;
     RECT  16.405 1.728 16.517 1.752 ;
     RECT  16.204 14.112 16.517 19.56 ;
     RECT  16.403 20.544 16.595 20.568 ;
     RECT  16.204 10.368 16.805 11.976 ;
     RECT  16.204 2.832 16.883 2.904 ;
     RECT  16.883 2.88 16.949 2.904 ;
     RECT  16.517 14.112 16.979 19.368 ;
     RECT  16.805 10.368 17.057 11.736 ;
     RECT  16.909 1.68 17.171 1.704 ;
     RECT  16.204 3.984 17.197 4.008 ;
     RECT  17.197 3.168 17.315 4.008 ;
     RECT  17.315 3.984 17.405 4.008 ;
     RECT  16.204 5.136 17.405 7.992 ;
     RECT  17.405 3.984 17.509 7.992 ;
     RECT  17.509 3.984 17.596 8.712 ;
     RECT  17.261 1.152 18.179 1.176 ;
     RECT  18.061 2.64 18.277 2.664 ;
     RECT  18.277 1.632 18.373 2.664 ;
     RECT  17.596 3.984 18.373 8.472 ;
     RECT  16.979 16.944 18.373 19.368 ;
     RECT  16.979 14.112 18.469 15.864 ;
     RECT  18.373 16.848 18.469 19.368 ;
     RECT  18.469 14.112 18.524 19.368 ;
     RECT  18.373 1.632 18.608 8.472 ;
     RECT  17.057 11.184 18.608 11.736 ;
     RECT  16.204 13.104 18.608 13.128 ;
     RECT  18.524 14.112 18.608 19.608 ;
     RECT  17.461 0.144 18.755 0.168 ;
     RECT  18.608 1.632 18.785 19.608 ;
     RECT  18.785 1.632 18.904 19.56 ;
     RECT  18.904 19.296 18.965 19.56 ;
     RECT  18.904 1.632 19.189 8.472 ;
     RECT  19.189 1.152 19.361 8.472 ;
     RECT  19.361 1.152 19.907 1.176 ;
     RECT  19.361 2.496 19.948 8.472 ;
     RECT  18.904 14.112 20.197 18.12 ;
     RECT  18.965 19.296 20.197 19.368 ;
     RECT  19.948 3.408 20.917 8.472 ;
     RECT  20.917 3.36 21.013 8.472 ;
     RECT  20.197 14.112 21.229 19.368 ;
     RECT  21.013 1.92 21.308 8.472 ;
     RECT  18.904 13.104 21.308 13.128 ;
     RECT  21.229 14.112 21.308 19.608 ;
     RECT  21.109 21.408 21.347 21.432 ;
     RECT  21.308 1.92 21.445 19.608 ;
     RECT  21.445 1.728 21.491 19.608 ;
     RECT  21.491 1.728 21.604 19.56 ;
     RECT  21.604 1.728 21.635 6.264 ;
     RECT  21.013 0.096 21.701 0.12 ;
     RECT  21.604 12.816 21.701 17.736 ;
     RECT  21.604 18.816 21.701 19.56 ;
     RECT  21.604 7.44 21.853 8.04 ;
     RECT  21.701 18.816 21.989 19.368 ;
     RECT  21.853 7.44 22.177 7.992 ;
     RECT  22.069 1.152 22.211 1.176 ;
     RECT  21.989 19.008 22.213 19.368 ;
     RECT  21.701 12.816 22.259 15.864 ;
     RECT  21.635 2.304 22.277 6.264 ;
     RECT  21.604 11.712 22.349 11.832 ;
     RECT  22.259 13.968 22.741 15.864 ;
     RECT  21.701 17.088 22.741 17.736 ;
     RECT  22.885 21.456 23.033 21.48 ;
     RECT  22.277 2.304 23.245 5.736 ;
     RECT  22.021 0.144 23.461 0.168 ;
     RECT  22.741 13.968 23.749 17.736 ;
     RECT  23.245 2.256 24.008 5.736 ;
     RECT  22.177 7.968 24.008 7.992 ;
     RECT  22.349 11.712 24.008 11.736 ;
     RECT  22.259 12.816 24.008 12.84 ;
     RECT  23.749 13.968 24.008 18.216 ;
     RECT  22.213 19.248 24.008 19.368 ;
     RECT  24.008 2.148 24.037 19.452 ;
     RECT  24.037 2.016 24.14 19.452 ;
     RECT  23.461 0.144 24.181 0.216 ;
     RECT  24.14 2.016 24.304 19.56 ;
     RECT  24.181 0.096 24.325 0.216 ;
     RECT  24.304 2.016 24.401 5.736 ;
     RECT  24.304 13.968 24.409 19.56 ;
     RECT  24.037 21.36 24.466 21.384 ;
     RECT  24.401 2.256 24.467 5.736 ;
     RECT  24.304 11.52 24.467 11.736 ;
     RECT  24.466 21.36 24.469 21.48 ;
     RECT  24.467 11.52 24.473 11.64 ;
     RECT  24.325 0.096 24.509 0.36 ;
     RECT  24.509 0.24 24.515 0.36 ;
     RECT  24.473 11.616 24.545 11.64 ;
     RECT  24.469 20.496 24.659 21.48 ;
     RECT  24.467 2.784 24.689 5.736 ;
     RECT  24.659 21.456 24.941 21.48 ;
     RECT  24.409 13.968 25.409 19.368 ;
     RECT  24.689 2.832 25.429 5.736 ;
     RECT  25.429 2.832 25.477 5.784 ;
     RECT  24.304 6.864 25.693 7.992 ;
     RECT  25.477 2.832 25.901 5.88 ;
     RECT  25.693 6.864 25.901 8.04 ;
     RECT  25.621 0.144 25.909 0.168 ;
     RECT  25.901 2.832 26.533 8.04 ;
     RECT  25.409 18.816 26.621 19.368 ;
     RECT  26.533 2.016 26.708 8.04 ;
     RECT  24.304 12.816 26.708 12.84 ;
     RECT  25.409 13.968 26.708 17.592 ;
     RECT  26.621 18.816 26.708 19.608 ;
     RECT  25.909 0.144 26.773 0.264 ;
     RECT  26.708 2.016 27.004 19.608 ;
     RECT  27.004 10.8 27.217 10.824 ;
     RECT  26.773 0.096 27.245 0.264 ;
     RECT  27.004 13.872 27.317 19.608 ;
     RECT  27.004 2.928 27.347 4.584 ;
     RECT  27.061 1.728 27.493 1.752 ;
     RECT  27.493 1.152 27.893 1.752 ;
     RECT  27.347 3.312 27.929 4.584 ;
     RECT  27.929 3.312 28.115 4.008 ;
     RECT  27.004 12.816 28.141 12.84 ;
     RECT  27.317 13.872 28.141 19.368 ;
     RECT  27.245 0.096 28.211 0.168 ;
     RECT  28.115 3.36 28.253 4.008 ;
     RECT  28.253 3.36 28.325 3.816 ;
     RECT  28.211 0.096 28.613 0.12 ;
     RECT  29.125 21.312 29.173 21.336 ;
     RECT  27.893 1.2 29.185 1.752 ;
     RECT  29.185 1.104 29.257 1.752 ;
     RECT  29.257 1.104 29.408 2.04 ;
     RECT  28.325 3.408 29.408 3.816 ;
     RECT  28.753 4.992 29.408 5.016 ;
     RECT  27.004 6.816 29.408 7.656 ;
     RECT  28.141 12.816 29.408 19.368 ;
     RECT  29.173 21.312 29.545 21.432 ;
     RECT  29.408 1.104 29.653 19.452 ;
     RECT  29.545 20.496 29.653 21.432 ;
     RECT  29.653 1.104 29.699 21.432 ;
     RECT  29.699 1.152 29.704 21.432 ;
     RECT  29.704 12.912 29.843 21.432 ;
     RECT  29.704 1.152 30.131 4.008 ;
     RECT  29.843 20.496 30.131 21.432 ;
     RECT  30.131 2.928 30.413 4.008 ;
     RECT  29.843 12.912 30.467 19.368 ;
     RECT  30.131 1.152 30.593 1.752 ;
     RECT  30.413 2.928 30.629 2.952 ;
     RECT  30.593 1.68 30.707 1.752 ;
     RECT  29.704 6.816 30.733 6.84 ;
     RECT  29.704 4.992 30.809 5.112 ;
     RECT  30.707 1.728 30.889 1.752 ;
     RECT  30.413 3.984 31.085 4.008 ;
     RECT  30.467 13.056 31.525 19.368 ;
     RECT  31.525 2.832 31.676 2.856 ;
     RECT  30.733 6.528 31.717 6.84 ;
     RECT  31.237 0.144 31.916 0.168 ;
     RECT  31.676 2.64 31.916 2.856 ;
     RECT  31.916 2.64 31.957 3 ;
     RECT  31.085 3.984 31.957 4.248 ;
     RECT  31.916 0.144 32.003 0.552 ;
     RECT  32.003 0.144 32.101 0.456 ;
     RECT  31.957 2.64 32.108 4.248 ;
     RECT  31.717 6.528 32.108 7.56 ;
     RECT  31.237 10.8 32.108 10.824 ;
     RECT  31.525 12.528 32.108 19.368 ;
     RECT  30.131 21.408 32.147 21.432 ;
     RECT  32.108 2.148 32.245 19.452 ;
     RECT  32.101 0.096 32.291 0.456 ;
     RECT  32.245 2.148 32.389 19.896 ;
     RECT  32.389 2.016 32.404 19.896 ;
     RECT  32.404 12.864 32.465 19.896 ;
     RECT  32.465 12.864 32.537 19.56 ;
     RECT  32.404 2.016 32.821 5.736 ;
     RECT  32.291 0.096 33.005 0.168 ;
     RECT  33.005 0.144 33.059 0.168 ;
     RECT  32.821 1.728 33.077 5.736 ;
     RECT  33.077 4.512 33.107 5.736 ;
     RECT  33.077 1.728 33.109 3.432 ;
     RECT  33.107 5.712 33.148 5.736 ;
     RECT  33.109 1.152 33.437 3.432 ;
     RECT  33.5 10.992 33.587 11.016 ;
     RECT  32.404 6.96 33.649 7.512 ;
     RECT  33.649 6.864 33.761 7.512 ;
     RECT  33.685 21.264 33.829 21.288 ;
     RECT  33.829 21.264 33.875 21.384 ;
     RECT  33.875 21.36 33.971 21.384 ;
     RECT  32.537 12.864 34.009 19.368 ;
     RECT  34.009 12.816 34.729 19.368 ;
     RECT  33.437 1.728 34.808 3.432 ;
     RECT  33.107 4.512 34.808 4.536 ;
     RECT  33.761 7.488 34.808 7.512 ;
     RECT  34.729 12.816 34.808 19.608 ;
     RECT  34.808 1.728 34.883 19.608 ;
     RECT  34.883 1.728 35.065 19.56 ;
     RECT  35.065 1.728 35.104 19.368 ;
     RECT  35.104 1.728 35.237 2.328 ;
     RECT  35.125 21.408 35.267 21.432 ;
     RECT  35.237 2.304 35.777 2.328 ;
     RECT  35.104 12.528 36.173 19.368 ;
     RECT  35.701 21.456 36.641 21.48 ;
     RECT  36.173 12.816 37.333 19.368 ;
     RECT  37.093 21.36 37.427 21.432 ;
     RECT  37.333 12.816 37.508 19.608 ;
     RECT  37.508 2.148 37.612 19.608 ;
     RECT  37.427 21.36 37.619 21.384 ;
     RECT  37.612 2.418 37.804 19.608 ;
     RECT  37.804 18.288 38.045 19.608 ;
     RECT  37.804 12.816 38.225 16.584 ;
     RECT  38.045 18.288 38.873 19.368 ;
     RECT  38.225 12.816 39.349 16.344 ;
     RECT  39.349 12.816 39.445 16.824 ;
     RECT  38.873 18.816 39.877 19.368 ;
     RECT  39.445 12.816 39.973 17.688 ;
     RECT  39.877 18.768 39.973 19.368 ;
     RECT  39.925 21.408 40.021 21.432 ;
     RECT  39.973 12.816 40.208 19.368 ;
     RECT  40.208 2.148 40.312 19.452 ;
     RECT  40.021 21.216 40.355 21.432 ;
     RECT  40.312 2.418 40.504 19.452 ;
     RECT  40.504 12.864 40.565 12.888 ;
     RECT  40.504 14.688 40.637 19.452 ;
     RECT  40.637 16.368 40.643 19.452 ;
     RECT  40.643 18.816 40.691 19.452 ;
     RECT  40.643 16.368 40.739 17.688 ;
     RECT  40.739 16.368 40.835 17.4 ;
     RECT  40.355 21.408 40.835 21.432 ;
     RECT  40.835 17.376 40.883 17.4 ;
     RECT  40.637 14.688 40.924 15.384 ;
     RECT  40.924 14.688 40.931 15.336 ;
     RECT  40.691 18.816 40.969 18.84 ;
     RECT  40.705 19.968 41.075 19.992 ;
     RECT  40.931 15.264 41.219 15.336 ;
     RECT  41.219 15.264 41.651 15.288 ;
     RECT  40.877 21.456 42.257 21.48 ;
     RECT  40.835 16.368 42.371 16.392 ;
    LAYER M5 ;
     RECT  9.936 0.016 10.392 0.131 ;
     RECT  14.544 0.016 28.248 0.131 ;
     RECT  14.688 0.131 28.248 0.179 ;
     RECT  10.08 0.131 10.392 0.611 ;
     RECT  14.832 0.179 28.248 1.187 ;
     RECT  10.08 0.611 10.248 1.763 ;
     RECT  14.976 1.187 28.248 1.763 ;
     RECT  29.52 0.016 34.008 2.137 ;
     RECT  2.4 2.137 2.52 2.151 ;
     RECT  5.1 2.137 5.22 2.151 ;
     RECT  7.8 2.137 7.92 2.151 ;
     RECT  10.5 2.137 10.62 2.151 ;
     RECT  13.2 2.137 13.32 2.151 ;
     RECT  29.4 2.137 34.92 2.151 ;
     RECT  37.5 2.137 37.62 2.151 ;
     RECT  40.2 2.137 40.32 2.151 ;
     RECT  15.12 1.763 28.248 2.339 ;
     RECT  29.4 2.151 35.112 3.443 ;
     RECT  15.9 2.339 28.248 3.827 ;
     RECT  15.9 3.827 28.2 4.019 ;
     RECT  29.4 3.443 33.144 4.019 ;
     RECT  31.104 4.019 33.144 4.259 ;
     RECT  17.28 4.019 28.104 4.595 ;
     RECT  15.9 4.019 16.212 5.077 ;
     RECT  18.48 4.595 27.012 5.123 ;
     RECT  17.28 4.595 17.304 5.219 ;
     RECT  18.6 5.123 27.012 5.747 ;
     RECT  18.6 5.747 22.152 6.803 ;
     RECT  15.264 5.077 16.212 6.805 ;
     RECT  28.08 4.595 28.104 6.805 ;
     RECT  29.4 4.019 29.712 6.805 ;
     RECT  24 5.747 27.012 6.899 ;
     RECT  31.728 4.259 33.144 6.995 ;
     RECT  20.352 6.803 22.152 7.475 ;
     RECT  28.08 6.805 29.712 7.475 ;
     RECT  18.6 6.803 19.32 7.523 ;
     RECT  20.352 7.475 21.816 7.523 ;
     RECT  31.728 6.995 32.412 7.571 ;
     RECT  21.3 7.523 21.816 8.051 ;
     RECT  25.728 6.899 27.012 8.051 ;
     RECT  17.52 7.093 17.544 8.723 ;
     RECT  26.7 8.051 27.012 10.789 ;
     RECT  32.1 7.571 32.412 10.789 ;
     RECT  15.264 6.805 16.344 10.883 ;
     RECT  13.2 2.151 13.512 11.173 ;
     RECT  13.2 11.173 13.656 11.701 ;
     RECT  21.3 8.051 21.612 11.797 ;
     RECT  13.2 11.701 14.232 11.941 ;
     RECT  34.8 3.443 35.112 12.757 ;
     RECT  28.944 7.475 29.712 12.901 ;
     RECT  31.392 10.789 32.412 12.901 ;
     RECT  33.552 10.981 33.576 12.949 ;
     RECT  34.8 12.757 35.928 12.949 ;
     RECT  33.552 12.949 35.928 12.997 ;
     RECT  21.3 11.797 22.248 13.139 ;
     RECT  28.512 12.901 32.412 13.237 ;
     RECT  40.2 2.151 40.512 13.285 ;
     RECT  10.5 2.151 10.812 13.573 ;
     RECT  33.552 12.997 36.264 13.573 ;
     RECT  10.224 13.573 10.812 13.909 ;
     RECT  33.552 13.573 36.36 13.909 ;
     RECT  10.176 13.909 10.812 14.005 ;
     RECT  40.032 13.285 40.512 14.005 ;
     RECT  10.176 14.005 11.496 14.101 ;
     RECT  12.48 11.941 14.232 14.101 ;
     RECT  28.512 13.237 32.52 14.101 ;
     RECT  21.3 13.139 21.612 14.149 ;
     RECT  18.6 7.523 18.912 14.197 ;
     RECT  21.024 14.149 21.612 14.197 ;
     RECT  39.936 14.005 40.512 14.197 ;
     RECT  10.176 14.101 14.232 14.293 ;
     RECT  15.264 10.883 16.212 14.293 ;
     RECT  24 6.899 24.552 14.485 ;
     RECT  18.096 14.197 19.32 14.629 ;
     RECT  10.176 14.293 16.212 14.677 ;
     RECT  39.024 14.197 40.512 14.677 ;
     RECT  7.8 2.151 8.112 14.725 ;
     RECT  17.616 14.629 19.32 14.773 ;
     RECT  26.7 10.789 27.192 14.773 ;
     RECT  28.512 14.101 32.568 14.821 ;
     RECT  33.552 13.909 36.456 14.821 ;
     RECT  28.512 14.821 36.456 15.157 ;
     RECT  37.5 2.151 37.812 15.157 ;
     RECT  39.024 14.677 40.92 15.253 ;
     RECT  10.176 14.677 16.344 15.301 ;
     RECT  17.616 14.773 19.368 15.301 ;
     RECT  26.7 14.773 27.528 15.349 ;
     RECT  28.512 15.157 37.812 15.349 ;
     RECT  10.176 15.301 19.368 15.443 ;
     RECT  20.832 14.197 21.612 15.733 ;
     RECT  7.8 14.725 8.952 15.829 ;
     RECT  10.176 15.443 17.016 15.829 ;
     RECT  39.024 15.253 41.64 16.067 ;
     RECT  20.688 15.733 21.612 16.069 ;
     RECT  26.7 15.349 37.812 16.069 ;
     RECT  18 15.443 19.368 16.117 ;
     RECT  20.4 16.069 21.612 16.117 ;
     RECT  23.328 14.485 24.552 16.309 ;
     RECT  39.36 16.067 41.64 16.357 ;
     RECT  7.8 15.829 17.016 16.501 ;
     RECT  7.392 16.501 17.016 16.835 ;
     RECT  25.968 16.069 37.812 16.835 ;
     RECT  39.36 16.357 42.36 16.835 ;
     RECT  22.752 16.309 24.552 16.933 ;
     RECT  18 16.117 21.612 17.077 ;
     RECT  22.752 16.933 24.936 17.077 ;
     RECT  18 17.077 24.936 17.171 ;
     RECT  7.392 16.835 14.376 17.507 ;
     RECT  7.8 17.507 14.376 17.699 ;
     RECT  39.456 16.835 42.36 17.699 ;
     RECT  11.904 17.699 14.376 17.843 ;
     RECT  15.36 16.835 17.016 18.133 ;
     RECT  18.096 17.171 22.632 18.133 ;
     RECT  24 17.171 24.936 18.181 ;
     RECT  5.1 2.151 5.412 18.805 ;
     RECT  7.8 17.699 10.812 18.805 ;
     RECT  11.904 17.843 14.184 18.805 ;
     RECT  15.36 18.133 22.632 18.805 ;
     RECT  23.76 18.181 24.936 18.805 ;
     RECT  26.7 16.835 37.812 18.805 ;
     RECT  39.888 17.699 42.36 18.805 ;
     RECT  7.488 18.805 22.632 19.237 ;
     RECT  23.76 18.805 42.36 19.237 ;
     RECT  5.1 18.805 6.504 19.285 ;
     RECT  7.488 19.237 42.36 19.285 ;
     RECT  5.1 19.285 42.36 19.333 ;
     RECT  2.4 2.151 2.712 19.449 ;
     RECT  2.4 19.449 2.52 19.463 ;
     RECT  4.464 19.333 42.36 21.443 ;
     RECT  4.464 21.443 13.56 21.584 ;
     RECT  14.544 21.443 42.36 21.584 ;
  END
END qkd_seq_xd_sel_r
END LIBRARY
